VERSION 5.7 ;
BUSBITCHARS "[]" ;
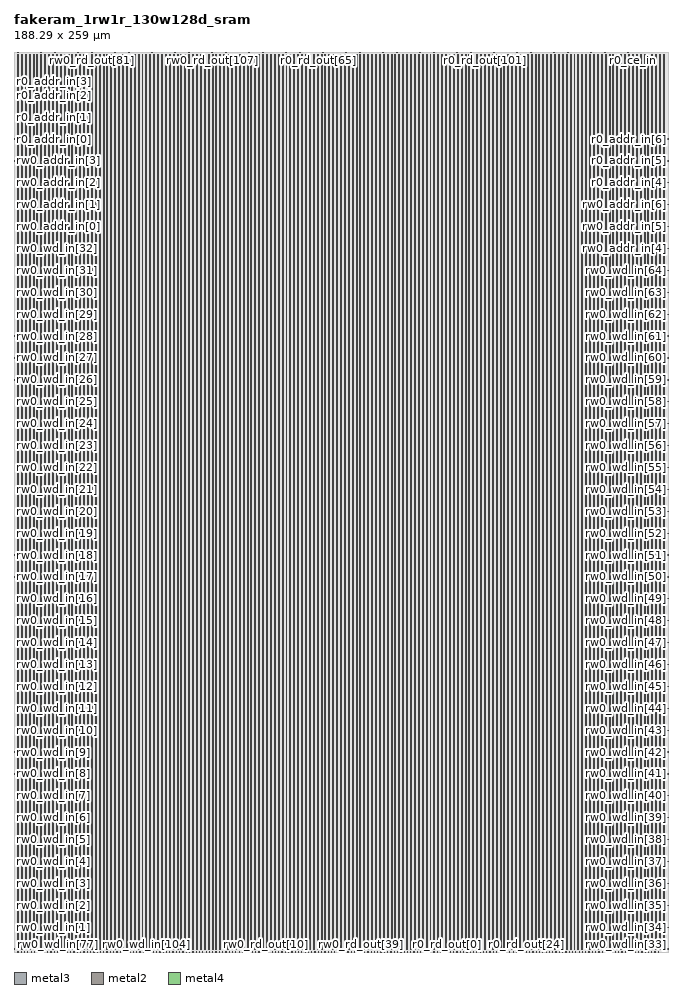
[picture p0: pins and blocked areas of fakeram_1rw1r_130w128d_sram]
MACRO fakeram_1rw1r_130w128d_sram
  FOREIGN fakeram_1rw1r_130w128d_sram 0 0 ;
  SYMMETRY X Y R90 ;
  SIZE 188.290 BY 259.000 ;
  CLASS BLOCK ;
  PIN rw0_wd_in[0]
    DIRECTION INPUT ;
    USE SIGNAL ;
    SHAPE ABUTMENT ;
    PORT
      LAYER metal3 ;
      RECT 0.000 0.805 0.210 0.875 ;
    END
  END rw0_wd_in[0]
  PIN rw0_wd_in[1]
    DIRECTION INPUT ;
    USE SIGNAL ;
    SHAPE ABUTMENT ;
    PORT
      LAYER metal3 ;
      RECT 0.000 7.105 0.210 7.175 ;
    END
  END rw0_wd_in[1]
  PIN rw0_wd_in[2]
    DIRECTION INPUT ;
    USE SIGNAL ;
    SHAPE ABUTMENT ;
    PORT
      LAYER metal3 ;
      RECT 0.000 13.405 0.210 13.475 ;
    END
  END rw0_wd_in[2]
  PIN rw0_wd_in[3]
    DIRECTION INPUT ;
    USE SIGNAL ;
    SHAPE ABUTMENT ;
    PORT
      LAYER metal3 ;
      RECT 0.000 19.705 0.210 19.775 ;
    END
  END rw0_wd_in[3]
  PIN rw0_wd_in[4]
    DIRECTION INPUT ;
    USE SIGNAL ;
    SHAPE ABUTMENT ;
    PORT
      LAYER metal3 ;
      RECT 0.000 26.005 0.210 26.075 ;
    END
  END rw0_wd_in[4]
  PIN rw0_wd_in[5]
    DIRECTION INPUT ;
    USE SIGNAL ;
    SHAPE ABUTMENT ;
    PORT
      LAYER metal3 ;
      RECT 0.000 32.305 0.210 32.375 ;
    END
  END rw0_wd_in[5]
  PIN rw0_wd_in[6]
    DIRECTION INPUT ;
    USE SIGNAL ;
    SHAPE ABUTMENT ;
    PORT
      LAYER metal3 ;
      RECT 0.000 38.605 0.210 38.675 ;
    END
  END rw0_wd_in[6]
  PIN rw0_wd_in[7]
    DIRECTION INPUT ;
    USE SIGNAL ;
    SHAPE ABUTMENT ;
    PORT
      LAYER metal3 ;
      RECT 0.000 44.905 0.210 44.975 ;
    END
  END rw0_wd_in[7]
  PIN rw0_wd_in[8]
    DIRECTION INPUT ;
    USE SIGNAL ;
    SHAPE ABUTMENT ;
    PORT
      LAYER metal3 ;
      RECT 0.000 51.205 0.210 51.275 ;
    END
  END rw0_wd_in[8]
  PIN rw0_wd_in[9]
    DIRECTION INPUT ;
    USE SIGNAL ;
    SHAPE ABUTMENT ;
    PORT
      LAYER metal3 ;
      RECT 0.000 57.505 0.210 57.575 ;
    END
  END rw0_wd_in[9]
  PIN rw0_wd_in[10]
    DIRECTION INPUT ;
    USE SIGNAL ;
    SHAPE ABUTMENT ;
    PORT
      LAYER metal3 ;
      RECT 0.000 63.805 0.210 63.875 ;
    END
  END rw0_wd_in[10]
  PIN rw0_wd_in[11]
    DIRECTION INPUT ;
    USE SIGNAL ;
    SHAPE ABUTMENT ;
    PORT
      LAYER metal3 ;
      RECT 0.000 70.105 0.210 70.175 ;
    END
  END rw0_wd_in[11]
  PIN rw0_wd_in[12]
    DIRECTION INPUT ;
    USE SIGNAL ;
    SHAPE ABUTMENT ;
    PORT
      LAYER metal3 ;
      RECT 0.000 76.405 0.210 76.475 ;
    END
  END rw0_wd_in[12]
  PIN rw0_wd_in[13]
    DIRECTION INPUT ;
    USE SIGNAL ;
    SHAPE ABUTMENT ;
    PORT
      LAYER metal3 ;
      RECT 0.000 82.705 0.210 82.775 ;
    END
  END rw0_wd_in[13]
  PIN rw0_wd_in[14]
    DIRECTION INPUT ;
    USE SIGNAL ;
    SHAPE ABUTMENT ;
    PORT
      LAYER metal3 ;
      RECT 0.000 89.005 0.210 89.075 ;
    END
  END rw0_wd_in[14]
  PIN rw0_wd_in[15]
    DIRECTION INPUT ;
    USE SIGNAL ;
    SHAPE ABUTMENT ;
    PORT
      LAYER metal3 ;
      RECT 0.000 95.305 0.210 95.375 ;
    END
  END rw0_wd_in[15]
  PIN rw0_wd_in[16]
    DIRECTION INPUT ;
    USE SIGNAL ;
    SHAPE ABUTMENT ;
    PORT
      LAYER metal3 ;
      RECT 0.000 101.605 0.210 101.675 ;
    END
  END rw0_wd_in[16]
  PIN rw0_wd_in[17]
    DIRECTION INPUT ;
    USE SIGNAL ;
    SHAPE ABUTMENT ;
    PORT
      LAYER metal3 ;
      RECT 0.000 107.905 0.210 107.975 ;
    END
  END rw0_wd_in[17]
  PIN rw0_wd_in[18]
    DIRECTION INPUT ;
    USE SIGNAL ;
    SHAPE ABUTMENT ;
    PORT
      LAYER metal3 ;
      RECT 0.000 114.205 0.210 114.275 ;
    END
  END rw0_wd_in[18]
  PIN rw0_wd_in[19]
    DIRECTION INPUT ;
    USE SIGNAL ;
    SHAPE ABUTMENT ;
    PORT
      LAYER metal3 ;
      RECT 0.000 120.505 0.210 120.575 ;
    END
  END rw0_wd_in[19]
  PIN rw0_wd_in[20]
    DIRECTION INPUT ;
    USE SIGNAL ;
    SHAPE ABUTMENT ;
    PORT
      LAYER metal3 ;
      RECT 0.000 126.805 0.210 126.875 ;
    END
  END rw0_wd_in[20]
  PIN rw0_wd_in[21]
    DIRECTION INPUT ;
    USE SIGNAL ;
    SHAPE ABUTMENT ;
    PORT
      LAYER metal3 ;
      RECT 0.000 133.105 0.210 133.175 ;
    END
  END rw0_wd_in[21]
  PIN rw0_wd_in[22]
    DIRECTION INPUT ;
    USE SIGNAL ;
    SHAPE ABUTMENT ;
    PORT
      LAYER metal3 ;
      RECT 0.000 139.405 0.210 139.475 ;
    END
  END rw0_wd_in[22]
  PIN rw0_wd_in[23]
    DIRECTION INPUT ;
    USE SIGNAL ;
    SHAPE ABUTMENT ;
    PORT
      LAYER metal3 ;
      RECT 0.000 145.705 0.210 145.775 ;
    END
  END rw0_wd_in[23]
  PIN rw0_wd_in[24]
    DIRECTION INPUT ;
    USE SIGNAL ;
    SHAPE ABUTMENT ;
    PORT
      LAYER metal3 ;
      RECT 0.000 152.005 0.210 152.075 ;
    END
  END rw0_wd_in[24]
  PIN rw0_wd_in[25]
    DIRECTION INPUT ;
    USE SIGNAL ;
    SHAPE ABUTMENT ;
    PORT
      LAYER metal3 ;
      RECT 0.000 158.305 0.210 158.375 ;
    END
  END rw0_wd_in[25]
  PIN rw0_wd_in[26]
    DIRECTION INPUT ;
    USE SIGNAL ;
    SHAPE ABUTMENT ;
    PORT
      LAYER metal3 ;
      RECT 0.000 164.605 0.210 164.675 ;
    END
  END rw0_wd_in[26]
  PIN rw0_wd_in[27]
    DIRECTION INPUT ;
    USE SIGNAL ;
    SHAPE ABUTMENT ;
    PORT
      LAYER metal3 ;
      RECT 0.000 170.905 0.210 170.975 ;
    END
  END rw0_wd_in[27]
  PIN rw0_wd_in[28]
    DIRECTION INPUT ;
    USE SIGNAL ;
    SHAPE ABUTMENT ;
    PORT
      LAYER metal3 ;
      RECT 0.000 177.205 0.210 177.275 ;
    END
  END rw0_wd_in[28]
  PIN rw0_wd_in[29]
    DIRECTION INPUT ;
    USE SIGNAL ;
    SHAPE ABUTMENT ;
    PORT
      LAYER metal3 ;
      RECT 0.000 183.505 0.210 183.575 ;
    END
  END rw0_wd_in[29]
  PIN rw0_wd_in[30]
    DIRECTION INPUT ;
    USE SIGNAL ;
    SHAPE ABUTMENT ;
    PORT
      LAYER metal3 ;
      RECT 0.000 189.805 0.210 189.875 ;
    END
  END rw0_wd_in[30]
  PIN rw0_wd_in[31]
    DIRECTION INPUT ;
    USE SIGNAL ;
    SHAPE ABUTMENT ;
    PORT
      LAYER metal3 ;
      RECT 0.000 196.105 0.210 196.175 ;
    END
  END rw0_wd_in[31]
  PIN rw0_wd_in[32]
    DIRECTION INPUT ;
    USE SIGNAL ;
    SHAPE ABUTMENT ;
    PORT
      LAYER metal3 ;
      RECT 0.000 202.405 0.210 202.475 ;
    END
  END rw0_wd_in[32]
  PIN rw0_wd_in[33]
    DIRECTION INPUT ;
    USE SIGNAL ;
    SHAPE ABUTMENT ;
    PORT
      LAYER metal3 ;
      RECT 188.080 0.805 188.290 0.875 ;
    END
  END rw0_wd_in[33]
  PIN rw0_wd_in[34]
    DIRECTION INPUT ;
    USE SIGNAL ;
    SHAPE ABUTMENT ;
    PORT
      LAYER metal3 ;
      RECT 188.080 7.105 188.290 7.175 ;
    END
  END rw0_wd_in[34]
  PIN rw0_wd_in[35]
    DIRECTION INPUT ;
    USE SIGNAL ;
    SHAPE ABUTMENT ;
    PORT
      LAYER metal3 ;
      RECT 188.080 13.405 188.290 13.475 ;
    END
  END rw0_wd_in[35]
  PIN rw0_wd_in[36]
    DIRECTION INPUT ;
    USE SIGNAL ;
    SHAPE ABUTMENT ;
    PORT
      LAYER metal3 ;
      RECT 188.080 19.705 188.290 19.775 ;
    END
  END rw0_wd_in[36]
  PIN rw0_wd_in[37]
    DIRECTION INPUT ;
    USE SIGNAL ;
    SHAPE ABUTMENT ;
    PORT
      LAYER metal3 ;
      RECT 188.080 26.005 188.290 26.075 ;
    END
  END rw0_wd_in[37]
  PIN rw0_wd_in[38]
    DIRECTION INPUT ;
    USE SIGNAL ;
    SHAPE ABUTMENT ;
    PORT
      LAYER metal3 ;
      RECT 188.080 32.305 188.290 32.375 ;
    END
  END rw0_wd_in[38]
  PIN rw0_wd_in[39]
    DIRECTION INPUT ;
    USE SIGNAL ;
    SHAPE ABUTMENT ;
    PORT
      LAYER metal3 ;
      RECT 188.080 38.605 188.290 38.675 ;
    END
  END rw0_wd_in[39]
  PIN rw0_wd_in[40]
    DIRECTION INPUT ;
    USE SIGNAL ;
    SHAPE ABUTMENT ;
    PORT
      LAYER metal3 ;
      RECT 188.080 44.905 188.290 44.975 ;
    END
  END rw0_wd_in[40]
  PIN rw0_wd_in[41]
    DIRECTION INPUT ;
    USE SIGNAL ;
    SHAPE ABUTMENT ;
    PORT
      LAYER metal3 ;
      RECT 188.080 51.205 188.290 51.275 ;
    END
  END rw0_wd_in[41]
  PIN rw0_wd_in[42]
    DIRECTION INPUT ;
    USE SIGNAL ;
    SHAPE ABUTMENT ;
    PORT
      LAYER metal3 ;
      RECT 188.080 57.505 188.290 57.575 ;
    END
  END rw0_wd_in[42]
  PIN rw0_wd_in[43]
    DIRECTION INPUT ;
    USE SIGNAL ;
    SHAPE ABUTMENT ;
    PORT
      LAYER metal3 ;
      RECT 188.080 63.805 188.290 63.875 ;
    END
  END rw0_wd_in[43]
  PIN rw0_wd_in[44]
    DIRECTION INPUT ;
    USE SIGNAL ;
    SHAPE ABUTMENT ;
    PORT
      LAYER metal3 ;
      RECT 188.080 70.105 188.290 70.175 ;
    END
  END rw0_wd_in[44]
  PIN rw0_wd_in[45]
    DIRECTION INPUT ;
    USE SIGNAL ;
    SHAPE ABUTMENT ;
    PORT
      LAYER metal3 ;
      RECT 188.080 76.405 188.290 76.475 ;
    END
  END rw0_wd_in[45]
  PIN rw0_wd_in[46]
    DIRECTION INPUT ;
    USE SIGNAL ;
    SHAPE ABUTMENT ;
    PORT
      LAYER metal3 ;
      RECT 188.080 82.705 188.290 82.775 ;
    END
  END rw0_wd_in[46]
  PIN rw0_wd_in[47]
    DIRECTION INPUT ;
    USE SIGNAL ;
    SHAPE ABUTMENT ;
    PORT
      LAYER metal3 ;
      RECT 188.080 89.005 188.290 89.075 ;
    END
  END rw0_wd_in[47]
  PIN rw0_wd_in[48]
    DIRECTION INPUT ;
    USE SIGNAL ;
    SHAPE ABUTMENT ;
    PORT
      LAYER metal3 ;
      RECT 188.080 95.305 188.290 95.375 ;
    END
  END rw0_wd_in[48]
  PIN rw0_wd_in[49]
    DIRECTION INPUT ;
    USE SIGNAL ;
    SHAPE ABUTMENT ;
    PORT
      LAYER metal3 ;
      RECT 188.080 101.605 188.290 101.675 ;
    END
  END rw0_wd_in[49]
  PIN rw0_wd_in[50]
    DIRECTION INPUT ;
    USE SIGNAL ;
    SHAPE ABUTMENT ;
    PORT
      LAYER metal3 ;
      RECT 188.080 107.905 188.290 107.975 ;
    END
  END rw0_wd_in[50]
  PIN rw0_wd_in[51]
    DIRECTION INPUT ;
    USE SIGNAL ;
    SHAPE ABUTMENT ;
    PORT
      LAYER metal3 ;
      RECT 188.080 114.205 188.290 114.275 ;
    END
  END rw0_wd_in[51]
  PIN rw0_wd_in[52]
    DIRECTION INPUT ;
    USE SIGNAL ;
    SHAPE ABUTMENT ;
    PORT
      LAYER metal3 ;
      RECT 188.080 120.505 188.290 120.575 ;
    END
  END rw0_wd_in[52]
  PIN rw0_wd_in[53]
    DIRECTION INPUT ;
    USE SIGNAL ;
    SHAPE ABUTMENT ;
    PORT
      LAYER metal3 ;
      RECT 188.080 126.805 188.290 126.875 ;
    END
  END rw0_wd_in[53]
  PIN rw0_wd_in[54]
    DIRECTION INPUT ;
    USE SIGNAL ;
    SHAPE ABUTMENT ;
    PORT
      LAYER metal3 ;
      RECT 188.080 133.105 188.290 133.175 ;
    END
  END rw0_wd_in[54]
  PIN rw0_wd_in[55]
    DIRECTION INPUT ;
    USE SIGNAL ;
    SHAPE ABUTMENT ;
    PORT
      LAYER metal3 ;
      RECT 188.080 139.405 188.290 139.475 ;
    END
  END rw0_wd_in[55]
  PIN rw0_wd_in[56]
    DIRECTION INPUT ;
    USE SIGNAL ;
    SHAPE ABUTMENT ;
    PORT
      LAYER metal3 ;
      RECT 188.080 145.705 188.290 145.775 ;
    END
  END rw0_wd_in[56]
  PIN rw0_wd_in[57]
    DIRECTION INPUT ;
    USE SIGNAL ;
    SHAPE ABUTMENT ;
    PORT
      LAYER metal3 ;
      RECT 188.080 152.005 188.290 152.075 ;
    END
  END rw0_wd_in[57]
  PIN rw0_wd_in[58]
    DIRECTION INPUT ;
    USE SIGNAL ;
    SHAPE ABUTMENT ;
    PORT
      LAYER metal3 ;
      RECT 188.080 158.305 188.290 158.375 ;
    END
  END rw0_wd_in[58]
  PIN rw0_wd_in[59]
    DIRECTION INPUT ;
    USE SIGNAL ;
    SHAPE ABUTMENT ;
    PORT
      LAYER metal3 ;
      RECT 188.080 164.605 188.290 164.675 ;
    END
  END rw0_wd_in[59]
  PIN rw0_wd_in[60]
    DIRECTION INPUT ;
    USE SIGNAL ;
    SHAPE ABUTMENT ;
    PORT
      LAYER metal3 ;
      RECT 188.080 170.905 188.290 170.975 ;
    END
  END rw0_wd_in[60]
  PIN rw0_wd_in[61]
    DIRECTION INPUT ;
    USE SIGNAL ;
    SHAPE ABUTMENT ;
    PORT
      LAYER metal3 ;
      RECT 188.080 177.205 188.290 177.275 ;
    END
  END rw0_wd_in[61]
  PIN rw0_wd_in[62]
    DIRECTION INPUT ;
    USE SIGNAL ;
    SHAPE ABUTMENT ;
    PORT
      LAYER metal3 ;
      RECT 188.080 183.505 188.290 183.575 ;
    END
  END rw0_wd_in[62]
  PIN rw0_wd_in[63]
    DIRECTION INPUT ;
    USE SIGNAL ;
    SHAPE ABUTMENT ;
    PORT
      LAYER metal3 ;
      RECT 188.080 189.805 188.290 189.875 ;
    END
  END rw0_wd_in[63]
  PIN rw0_wd_in[64]
    DIRECTION INPUT ;
    USE SIGNAL ;
    SHAPE ABUTMENT ;
    PORT
      LAYER metal3 ;
      RECT 188.080 196.105 188.290 196.175 ;
    END
  END rw0_wd_in[64]
  PIN rw0_wd_in[65]
    DIRECTION INPUT ;
    USE SIGNAL ;
    SHAPE ABUTMENT ;
    PORT
      LAYER metal2 ;
      RECT 1.105 0.000 1.175 0.210 ;
    END
  END rw0_wd_in[65]
  PIN rw0_wd_in[66]
    DIRECTION INPUT ;
    USE SIGNAL ;
    SHAPE ABUTMENT ;
    PORT
      LAYER metal2 ;
      RECT 2.055 0.000 2.125 0.210 ;
    END
  END rw0_wd_in[66]
  PIN rw0_wd_in[67]
    DIRECTION INPUT ;
    USE SIGNAL ;
    SHAPE ABUTMENT ;
    PORT
      LAYER metal2 ;
      RECT 3.005 0.000 3.075 0.210 ;
    END
  END rw0_wd_in[67]
  PIN rw0_wd_in[68]
    DIRECTION INPUT ;
    USE SIGNAL ;
    SHAPE ABUTMENT ;
    PORT
      LAYER metal2 ;
      RECT 3.955 0.000 4.025 0.210 ;
    END
  END rw0_wd_in[68]
  PIN rw0_wd_in[69]
    DIRECTION INPUT ;
    USE SIGNAL ;
    SHAPE ABUTMENT ;
    PORT
      LAYER metal2 ;
      RECT 4.905 0.000 4.975 0.210 ;
    END
  END rw0_wd_in[69]
  PIN rw0_wd_in[70]
    DIRECTION INPUT ;
    USE SIGNAL ;
    SHAPE ABUTMENT ;
    PORT
      LAYER metal2 ;
      RECT 5.855 0.000 5.925 0.210 ;
    END
  END rw0_wd_in[70]
  PIN rw0_wd_in[71]
    DIRECTION INPUT ;
    USE SIGNAL ;
    SHAPE ABUTMENT ;
    PORT
      LAYER metal2 ;
      RECT 6.805 0.000 6.875 0.210 ;
    END
  END rw0_wd_in[71]
  PIN rw0_wd_in[72]
    DIRECTION INPUT ;
    USE SIGNAL ;
    SHAPE ABUTMENT ;
    PORT
      LAYER metal2 ;
      RECT 7.755 0.000 7.825 0.210 ;
    END
  END rw0_wd_in[72]
  PIN rw0_wd_in[73]
    DIRECTION INPUT ;
    USE SIGNAL ;
    SHAPE ABUTMENT ;
    PORT
      LAYER metal2 ;
      RECT 8.705 0.000 8.775 0.210 ;
    END
  END rw0_wd_in[73]
  PIN rw0_wd_in[74]
    DIRECTION INPUT ;
    USE SIGNAL ;
    SHAPE ABUTMENT ;
    PORT
      LAYER metal2 ;
      RECT 9.655 0.000 9.725 0.210 ;
    END
  END rw0_wd_in[74]
  PIN rw0_wd_in[75]
    DIRECTION INPUT ;
    USE SIGNAL ;
    SHAPE ABUTMENT ;
    PORT
      LAYER metal2 ;
      RECT 10.605 0.000 10.675 0.210 ;
    END
  END rw0_wd_in[75]
  PIN rw0_wd_in[76]
    DIRECTION INPUT ;
    USE SIGNAL ;
    SHAPE ABUTMENT ;
    PORT
      LAYER metal2 ;
      RECT 11.555 0.000 11.625 0.210 ;
    END
  END rw0_wd_in[76]
  PIN rw0_wd_in[77]
    DIRECTION INPUT ;
    USE SIGNAL ;
    SHAPE ABUTMENT ;
    PORT
      LAYER metal2 ;
      RECT 12.505 0.000 12.575 0.210 ;
    END
  END rw0_wd_in[77]
  PIN rw0_wd_in[78]
    DIRECTION INPUT ;
    USE SIGNAL ;
    SHAPE ABUTMENT ;
    PORT
      LAYER metal2 ;
      RECT 13.455 0.000 13.525 0.210 ;
    END
  END rw0_wd_in[78]
  PIN rw0_wd_in[79]
    DIRECTION INPUT ;
    USE SIGNAL ;
    SHAPE ABUTMENT ;
    PORT
      LAYER metal2 ;
      RECT 14.405 0.000 14.475 0.210 ;
    END
  END rw0_wd_in[79]
  PIN rw0_wd_in[80]
    DIRECTION INPUT ;
    USE SIGNAL ;
    SHAPE ABUTMENT ;
    PORT
      LAYER metal2 ;
      RECT 15.355 0.000 15.425 0.210 ;
    END
  END rw0_wd_in[80]
  PIN rw0_wd_in[81]
    DIRECTION INPUT ;
    USE SIGNAL ;
    SHAPE ABUTMENT ;
    PORT
      LAYER metal2 ;
      RECT 16.305 0.000 16.375 0.210 ;
    END
  END rw0_wd_in[81]
  PIN rw0_wd_in[82]
    DIRECTION INPUT ;
    USE SIGNAL ;
    SHAPE ABUTMENT ;
    PORT
      LAYER metal2 ;
      RECT 17.255 0.000 17.325 0.210 ;
    END
  END rw0_wd_in[82]
  PIN rw0_wd_in[83]
    DIRECTION INPUT ;
    USE SIGNAL ;
    SHAPE ABUTMENT ;
    PORT
      LAYER metal2 ;
      RECT 18.205 0.000 18.275 0.210 ;
    END
  END rw0_wd_in[83]
  PIN rw0_wd_in[84]
    DIRECTION INPUT ;
    USE SIGNAL ;
    SHAPE ABUTMENT ;
    PORT
      LAYER metal2 ;
      RECT 19.155 0.000 19.225 0.210 ;
    END
  END rw0_wd_in[84]
  PIN rw0_wd_in[85]
    DIRECTION INPUT ;
    USE SIGNAL ;
    SHAPE ABUTMENT ;
    PORT
      LAYER metal2 ;
      RECT 20.105 0.000 20.175 0.210 ;
    END
  END rw0_wd_in[85]
  PIN rw0_wd_in[86]
    DIRECTION INPUT ;
    USE SIGNAL ;
    SHAPE ABUTMENT ;
    PORT
      LAYER metal2 ;
      RECT 21.055 0.000 21.125 0.210 ;
    END
  END rw0_wd_in[86]
  PIN rw0_wd_in[87]
    DIRECTION INPUT ;
    USE SIGNAL ;
    SHAPE ABUTMENT ;
    PORT
      LAYER metal2 ;
      RECT 22.005 0.000 22.075 0.210 ;
    END
  END rw0_wd_in[87]
  PIN rw0_wd_in[88]
    DIRECTION INPUT ;
    USE SIGNAL ;
    SHAPE ABUTMENT ;
    PORT
      LAYER metal2 ;
      RECT 22.955 0.000 23.025 0.210 ;
    END
  END rw0_wd_in[88]
  PIN rw0_wd_in[89]
    DIRECTION INPUT ;
    USE SIGNAL ;
    SHAPE ABUTMENT ;
    PORT
      LAYER metal2 ;
      RECT 23.905 0.000 23.975 0.210 ;
    END
  END rw0_wd_in[89]
  PIN rw0_wd_in[90]
    DIRECTION INPUT ;
    USE SIGNAL ;
    SHAPE ABUTMENT ;
    PORT
      LAYER metal2 ;
      RECT 24.855 0.000 24.925 0.210 ;
    END
  END rw0_wd_in[90]
  PIN rw0_wd_in[91]
    DIRECTION INPUT ;
    USE SIGNAL ;
    SHAPE ABUTMENT ;
    PORT
      LAYER metal2 ;
      RECT 25.805 0.000 25.875 0.210 ;
    END
  END rw0_wd_in[91]
  PIN rw0_wd_in[92]
    DIRECTION INPUT ;
    USE SIGNAL ;
    SHAPE ABUTMENT ;
    PORT
      LAYER metal2 ;
      RECT 26.755 0.000 26.825 0.210 ;
    END
  END rw0_wd_in[92]
  PIN rw0_wd_in[93]
    DIRECTION INPUT ;
    USE SIGNAL ;
    SHAPE ABUTMENT ;
    PORT
      LAYER metal2 ;
      RECT 27.705 0.000 27.775 0.210 ;
    END
  END rw0_wd_in[93]
  PIN rw0_wd_in[94]
    DIRECTION INPUT ;
    USE SIGNAL ;
    SHAPE ABUTMENT ;
    PORT
      LAYER metal2 ;
      RECT 28.655 0.000 28.725 0.210 ;
    END
  END rw0_wd_in[94]
  PIN rw0_wd_in[95]
    DIRECTION INPUT ;
    USE SIGNAL ;
    SHAPE ABUTMENT ;
    PORT
      LAYER metal2 ;
      RECT 29.605 0.000 29.675 0.210 ;
    END
  END rw0_wd_in[95]
  PIN rw0_wd_in[96]
    DIRECTION INPUT ;
    USE SIGNAL ;
    SHAPE ABUTMENT ;
    PORT
      LAYER metal2 ;
      RECT 30.555 0.000 30.625 0.210 ;
    END
  END rw0_wd_in[96]
  PIN rw0_wd_in[97]
    DIRECTION INPUT ;
    USE SIGNAL ;
    SHAPE ABUTMENT ;
    PORT
      LAYER metal2 ;
      RECT 31.505 0.000 31.575 0.210 ;
    END
  END rw0_wd_in[97]
  PIN rw0_wd_in[98]
    DIRECTION INPUT ;
    USE SIGNAL ;
    SHAPE ABUTMENT ;
    PORT
      LAYER metal2 ;
      RECT 32.455 0.000 32.525 0.210 ;
    END
  END rw0_wd_in[98]
  PIN rw0_wd_in[99]
    DIRECTION INPUT ;
    USE SIGNAL ;
    SHAPE ABUTMENT ;
    PORT
      LAYER metal2 ;
      RECT 33.405 0.000 33.475 0.210 ;
    END
  END rw0_wd_in[99]
  PIN rw0_wd_in[100]
    DIRECTION INPUT ;
    USE SIGNAL ;
    SHAPE ABUTMENT ;
    PORT
      LAYER metal2 ;
      RECT 34.355 0.000 34.425 0.210 ;
    END
  END rw0_wd_in[100]
  PIN rw0_wd_in[101]
    DIRECTION INPUT ;
    USE SIGNAL ;
    SHAPE ABUTMENT ;
    PORT
      LAYER metal2 ;
      RECT 35.305 0.000 35.375 0.210 ;
    END
  END rw0_wd_in[101]
  PIN rw0_wd_in[102]
    DIRECTION INPUT ;
    USE SIGNAL ;
    SHAPE ABUTMENT ;
    PORT
      LAYER metal2 ;
      RECT 36.255 0.000 36.325 0.210 ;
    END
  END rw0_wd_in[102]
  PIN rw0_wd_in[103]
    DIRECTION INPUT ;
    USE SIGNAL ;
    SHAPE ABUTMENT ;
    PORT
      LAYER metal2 ;
      RECT 37.205 0.000 37.275 0.210 ;
    END
  END rw0_wd_in[103]
  PIN rw0_wd_in[104]
    DIRECTION INPUT ;
    USE SIGNAL ;
    SHAPE ABUTMENT ;
    PORT
      LAYER metal2 ;
      RECT 38.155 0.000 38.225 0.210 ;
    END
  END rw0_wd_in[104]
  PIN rw0_wd_in[105]
    DIRECTION INPUT ;
    USE SIGNAL ;
    SHAPE ABUTMENT ;
    PORT
      LAYER metal2 ;
      RECT 39.105 0.000 39.175 0.210 ;
    END
  END rw0_wd_in[105]
  PIN rw0_wd_in[106]
    DIRECTION INPUT ;
    USE SIGNAL ;
    SHAPE ABUTMENT ;
    PORT
      LAYER metal2 ;
      RECT 40.055 0.000 40.125 0.210 ;
    END
  END rw0_wd_in[106]
  PIN rw0_wd_in[107]
    DIRECTION INPUT ;
    USE SIGNAL ;
    SHAPE ABUTMENT ;
    PORT
      LAYER metal2 ;
      RECT 41.005 0.000 41.075 0.210 ;
    END
  END rw0_wd_in[107]
  PIN rw0_wd_in[108]
    DIRECTION INPUT ;
    USE SIGNAL ;
    SHAPE ABUTMENT ;
    PORT
      LAYER metal2 ;
      RECT 41.955 0.000 42.025 0.210 ;
    END
  END rw0_wd_in[108]
  PIN rw0_wd_in[109]
    DIRECTION INPUT ;
    USE SIGNAL ;
    SHAPE ABUTMENT ;
    PORT
      LAYER metal2 ;
      RECT 42.905 0.000 42.975 0.210 ;
    END
  END rw0_wd_in[109]
  PIN rw0_wd_in[110]
    DIRECTION INPUT ;
    USE SIGNAL ;
    SHAPE ABUTMENT ;
    PORT
      LAYER metal2 ;
      RECT 43.855 0.000 43.925 0.210 ;
    END
  END rw0_wd_in[110]
  PIN rw0_wd_in[111]
    DIRECTION INPUT ;
    USE SIGNAL ;
    SHAPE ABUTMENT ;
    PORT
      LAYER metal2 ;
      RECT 44.805 0.000 44.875 0.210 ;
    END
  END rw0_wd_in[111]
  PIN rw0_wd_in[112]
    DIRECTION INPUT ;
    USE SIGNAL ;
    SHAPE ABUTMENT ;
    PORT
      LAYER metal2 ;
      RECT 45.755 0.000 45.825 0.210 ;
    END
  END rw0_wd_in[112]
  PIN rw0_wd_in[113]
    DIRECTION INPUT ;
    USE SIGNAL ;
    SHAPE ABUTMENT ;
    PORT
      LAYER metal2 ;
      RECT 46.705 0.000 46.775 0.210 ;
    END
  END rw0_wd_in[113]
  PIN rw0_wd_in[114]
    DIRECTION INPUT ;
    USE SIGNAL ;
    SHAPE ABUTMENT ;
    PORT
      LAYER metal2 ;
      RECT 47.655 0.000 47.725 0.210 ;
    END
  END rw0_wd_in[114]
  PIN rw0_wd_in[115]
    DIRECTION INPUT ;
    USE SIGNAL ;
    SHAPE ABUTMENT ;
    PORT
      LAYER metal2 ;
      RECT 48.605 0.000 48.675 0.210 ;
    END
  END rw0_wd_in[115]
  PIN rw0_wd_in[116]
    DIRECTION INPUT ;
    USE SIGNAL ;
    SHAPE ABUTMENT ;
    PORT
      LAYER metal2 ;
      RECT 49.555 0.000 49.625 0.210 ;
    END
  END rw0_wd_in[116]
  PIN rw0_wd_in[117]
    DIRECTION INPUT ;
    USE SIGNAL ;
    SHAPE ABUTMENT ;
    PORT
      LAYER metal2 ;
      RECT 50.505 0.000 50.575 0.210 ;
    END
  END rw0_wd_in[117]
  PIN rw0_wd_in[118]
    DIRECTION INPUT ;
    USE SIGNAL ;
    SHAPE ABUTMENT ;
    PORT
      LAYER metal2 ;
      RECT 51.455 0.000 51.525 0.210 ;
    END
  END rw0_wd_in[118]
  PIN rw0_wd_in[119]
    DIRECTION INPUT ;
    USE SIGNAL ;
    SHAPE ABUTMENT ;
    PORT
      LAYER metal2 ;
      RECT 52.405 0.000 52.475 0.210 ;
    END
  END rw0_wd_in[119]
  PIN rw0_wd_in[120]
    DIRECTION INPUT ;
    USE SIGNAL ;
    SHAPE ABUTMENT ;
    PORT
      LAYER metal2 ;
      RECT 53.355 0.000 53.425 0.210 ;
    END
  END rw0_wd_in[120]
  PIN rw0_wd_in[121]
    DIRECTION INPUT ;
    USE SIGNAL ;
    SHAPE ABUTMENT ;
    PORT
      LAYER metal2 ;
      RECT 54.305 0.000 54.375 0.210 ;
    END
  END rw0_wd_in[121]
  PIN rw0_wd_in[122]
    DIRECTION INPUT ;
    USE SIGNAL ;
    SHAPE ABUTMENT ;
    PORT
      LAYER metal2 ;
      RECT 55.255 0.000 55.325 0.210 ;
    END
  END rw0_wd_in[122]
  PIN rw0_wd_in[123]
    DIRECTION INPUT ;
    USE SIGNAL ;
    SHAPE ABUTMENT ;
    PORT
      LAYER metal2 ;
      RECT 56.205 0.000 56.275 0.210 ;
    END
  END rw0_wd_in[123]
  PIN rw0_wd_in[124]
    DIRECTION INPUT ;
    USE SIGNAL ;
    SHAPE ABUTMENT ;
    PORT
      LAYER metal2 ;
      RECT 57.155 0.000 57.225 0.210 ;
    END
  END rw0_wd_in[124]
  PIN rw0_wd_in[125]
    DIRECTION INPUT ;
    USE SIGNAL ;
    SHAPE ABUTMENT ;
    PORT
      LAYER metal2 ;
      RECT 58.105 0.000 58.175 0.210 ;
    END
  END rw0_wd_in[125]
  PIN rw0_wd_in[126]
    DIRECTION INPUT ;
    USE SIGNAL ;
    SHAPE ABUTMENT ;
    PORT
      LAYER metal2 ;
      RECT 59.055 0.000 59.125 0.210 ;
    END
  END rw0_wd_in[126]
  PIN rw0_wd_in[127]
    DIRECTION INPUT ;
    USE SIGNAL ;
    SHAPE ABUTMENT ;
    PORT
      LAYER metal2 ;
      RECT 60.005 0.000 60.075 0.210 ;
    END
  END rw0_wd_in[127]
  PIN rw0_wd_in[128]
    DIRECTION INPUT ;
    USE SIGNAL ;
    SHAPE ABUTMENT ;
    PORT
      LAYER metal2 ;
      RECT 60.955 0.000 61.025 0.210 ;
    END
  END rw0_wd_in[128]
  PIN rw0_wd_in[129]
    DIRECTION INPUT ;
    USE SIGNAL ;
    SHAPE ABUTMENT ;
    PORT
      LAYER metal2 ;
      RECT 61.905 0.000 61.975 0.210 ;
    END
  END rw0_wd_in[129]
  PIN rw0_rd_out[0]
    DIRECTION OUTPUT ;
    USE SIGNAL ;
    SHAPE ABUTMENT ;
    PORT
      LAYER metal2 ;
      RECT 62.855 0.000 62.925 0.210 ;
    END
  END rw0_rd_out[0]
  PIN rw0_rd_out[1]
    DIRECTION OUTPUT ;
    USE SIGNAL ;
    SHAPE ABUTMENT ;
    PORT
      LAYER metal2 ;
      RECT 63.805 0.000 63.875 0.210 ;
    END
  END rw0_rd_out[1]
  PIN rw0_rd_out[2]
    DIRECTION OUTPUT ;
    USE SIGNAL ;
    SHAPE ABUTMENT ;
    PORT
      LAYER metal2 ;
      RECT 64.755 0.000 64.825 0.210 ;
    END
  END rw0_rd_out[2]
  PIN rw0_rd_out[3]
    DIRECTION OUTPUT ;
    USE SIGNAL ;
    SHAPE ABUTMENT ;
    PORT
      LAYER metal2 ;
      RECT 65.705 0.000 65.775 0.210 ;
    END
  END rw0_rd_out[3]
  PIN rw0_rd_out[4]
    DIRECTION OUTPUT ;
    USE SIGNAL ;
    SHAPE ABUTMENT ;
    PORT
      LAYER metal2 ;
      RECT 66.655 0.000 66.725 0.210 ;
    END
  END rw0_rd_out[4]
  PIN rw0_rd_out[5]
    DIRECTION OUTPUT ;
    USE SIGNAL ;
    SHAPE ABUTMENT ;
    PORT
      LAYER metal2 ;
      RECT 67.605 0.000 67.675 0.210 ;
    END
  END rw0_rd_out[5]
  PIN rw0_rd_out[6]
    DIRECTION OUTPUT ;
    USE SIGNAL ;
    SHAPE ABUTMENT ;
    PORT
      LAYER metal2 ;
      RECT 68.555 0.000 68.625 0.210 ;
    END
  END rw0_rd_out[6]
  PIN rw0_rd_out[7]
    DIRECTION OUTPUT ;
    USE SIGNAL ;
    SHAPE ABUTMENT ;
    PORT
      LAYER metal2 ;
      RECT 69.505 0.000 69.575 0.210 ;
    END
  END rw0_rd_out[7]
  PIN rw0_rd_out[8]
    DIRECTION OUTPUT ;
    USE SIGNAL ;
    SHAPE ABUTMENT ;
    PORT
      LAYER metal2 ;
      RECT 70.455 0.000 70.525 0.210 ;
    END
  END rw0_rd_out[8]
  PIN rw0_rd_out[9]
    DIRECTION OUTPUT ;
    USE SIGNAL ;
    SHAPE ABUTMENT ;
    PORT
      LAYER metal2 ;
      RECT 71.405 0.000 71.475 0.210 ;
    END
  END rw0_rd_out[9]
  PIN rw0_rd_out[10]
    DIRECTION OUTPUT ;
    USE SIGNAL ;
    SHAPE ABUTMENT ;
    PORT
      LAYER metal2 ;
      RECT 72.355 0.000 72.425 0.210 ;
    END
  END rw0_rd_out[10]
  PIN rw0_rd_out[11]
    DIRECTION OUTPUT ;
    USE SIGNAL ;
    SHAPE ABUTMENT ;
    PORT
      LAYER metal2 ;
      RECT 73.305 0.000 73.375 0.210 ;
    END
  END rw0_rd_out[11]
  PIN rw0_rd_out[12]
    DIRECTION OUTPUT ;
    USE SIGNAL ;
    SHAPE ABUTMENT ;
    PORT
      LAYER metal2 ;
      RECT 74.255 0.000 74.325 0.210 ;
    END
  END rw0_rd_out[12]
  PIN rw0_rd_out[13]
    DIRECTION OUTPUT ;
    USE SIGNAL ;
    SHAPE ABUTMENT ;
    PORT
      LAYER metal2 ;
      RECT 75.205 0.000 75.275 0.210 ;
    END
  END rw0_rd_out[13]
  PIN rw0_rd_out[14]
    DIRECTION OUTPUT ;
    USE SIGNAL ;
    SHAPE ABUTMENT ;
    PORT
      LAYER metal2 ;
      RECT 76.155 0.000 76.225 0.210 ;
    END
  END rw0_rd_out[14]
  PIN rw0_rd_out[15]
    DIRECTION OUTPUT ;
    USE SIGNAL ;
    SHAPE ABUTMENT ;
    PORT
      LAYER metal2 ;
      RECT 77.105 0.000 77.175 0.210 ;
    END
  END rw0_rd_out[15]
  PIN rw0_rd_out[16]
    DIRECTION OUTPUT ;
    USE SIGNAL ;
    SHAPE ABUTMENT ;
    PORT
      LAYER metal2 ;
      RECT 78.055 0.000 78.125 0.210 ;
    END
  END rw0_rd_out[16]
  PIN rw0_rd_out[17]
    DIRECTION OUTPUT ;
    USE SIGNAL ;
    SHAPE ABUTMENT ;
    PORT
      LAYER metal2 ;
      RECT 79.005 0.000 79.075 0.210 ;
    END
  END rw0_rd_out[17]
  PIN rw0_rd_out[18]
    DIRECTION OUTPUT ;
    USE SIGNAL ;
    SHAPE ABUTMENT ;
    PORT
      LAYER metal2 ;
      RECT 79.955 0.000 80.025 0.210 ;
    END
  END rw0_rd_out[18]
  PIN rw0_rd_out[19]
    DIRECTION OUTPUT ;
    USE SIGNAL ;
    SHAPE ABUTMENT ;
    PORT
      LAYER metal2 ;
      RECT 80.905 0.000 80.975 0.210 ;
    END
  END rw0_rd_out[19]
  PIN rw0_rd_out[20]
    DIRECTION OUTPUT ;
    USE SIGNAL ;
    SHAPE ABUTMENT ;
    PORT
      LAYER metal2 ;
      RECT 81.855 0.000 81.925 0.210 ;
    END
  END rw0_rd_out[20]
  PIN rw0_rd_out[21]
    DIRECTION OUTPUT ;
    USE SIGNAL ;
    SHAPE ABUTMENT ;
    PORT
      LAYER metal2 ;
      RECT 82.805 0.000 82.875 0.210 ;
    END
  END rw0_rd_out[21]
  PIN rw0_rd_out[22]
    DIRECTION OUTPUT ;
    USE SIGNAL ;
    SHAPE ABUTMENT ;
    PORT
      LAYER metal2 ;
      RECT 83.755 0.000 83.825 0.210 ;
    END
  END rw0_rd_out[22]
  PIN rw0_rd_out[23]
    DIRECTION OUTPUT ;
    USE SIGNAL ;
    SHAPE ABUTMENT ;
    PORT
      LAYER metal2 ;
      RECT 84.705 0.000 84.775 0.210 ;
    END
  END rw0_rd_out[23]
  PIN rw0_rd_out[24]
    DIRECTION OUTPUT ;
    USE SIGNAL ;
    SHAPE ABUTMENT ;
    PORT
      LAYER metal2 ;
      RECT 85.655 0.000 85.725 0.210 ;
    END
  END rw0_rd_out[24]
  PIN rw0_rd_out[25]
    DIRECTION OUTPUT ;
    USE SIGNAL ;
    SHAPE ABUTMENT ;
    PORT
      LAYER metal2 ;
      RECT 86.605 0.000 86.675 0.210 ;
    END
  END rw0_rd_out[25]
  PIN rw0_rd_out[26]
    DIRECTION OUTPUT ;
    USE SIGNAL ;
    SHAPE ABUTMENT ;
    PORT
      LAYER metal2 ;
      RECT 87.555 0.000 87.625 0.210 ;
    END
  END rw0_rd_out[26]
  PIN rw0_rd_out[27]
    DIRECTION OUTPUT ;
    USE SIGNAL ;
    SHAPE ABUTMENT ;
    PORT
      LAYER metal2 ;
      RECT 88.505 0.000 88.575 0.210 ;
    END
  END rw0_rd_out[27]
  PIN rw0_rd_out[28]
    DIRECTION OUTPUT ;
    USE SIGNAL ;
    SHAPE ABUTMENT ;
    PORT
      LAYER metal2 ;
      RECT 89.455 0.000 89.525 0.210 ;
    END
  END rw0_rd_out[28]
  PIN rw0_rd_out[29]
    DIRECTION OUTPUT ;
    USE SIGNAL ;
    SHAPE ABUTMENT ;
    PORT
      LAYER metal2 ;
      RECT 90.405 0.000 90.475 0.210 ;
    END
  END rw0_rd_out[29]
  PIN rw0_rd_out[30]
    DIRECTION OUTPUT ;
    USE SIGNAL ;
    SHAPE ABUTMENT ;
    PORT
      LAYER metal2 ;
      RECT 91.355 0.000 91.425 0.210 ;
    END
  END rw0_rd_out[30]
  PIN rw0_rd_out[31]
    DIRECTION OUTPUT ;
    USE SIGNAL ;
    SHAPE ABUTMENT ;
    PORT
      LAYER metal2 ;
      RECT 92.305 0.000 92.375 0.210 ;
    END
  END rw0_rd_out[31]
  PIN rw0_rd_out[32]
    DIRECTION OUTPUT ;
    USE SIGNAL ;
    SHAPE ABUTMENT ;
    PORT
      LAYER metal2 ;
      RECT 93.255 0.000 93.325 0.210 ;
    END
  END rw0_rd_out[32]
  PIN rw0_rd_out[33]
    DIRECTION OUTPUT ;
    USE SIGNAL ;
    SHAPE ABUTMENT ;
    PORT
      LAYER metal2 ;
      RECT 94.205 0.000 94.275 0.210 ;
    END
  END rw0_rd_out[33]
  PIN rw0_rd_out[34]
    DIRECTION OUTPUT ;
    USE SIGNAL ;
    SHAPE ABUTMENT ;
    PORT
      LAYER metal2 ;
      RECT 95.155 0.000 95.225 0.210 ;
    END
  END rw0_rd_out[34]
  PIN rw0_rd_out[35]
    DIRECTION OUTPUT ;
    USE SIGNAL ;
    SHAPE ABUTMENT ;
    PORT
      LAYER metal2 ;
      RECT 96.105 0.000 96.175 0.210 ;
    END
  END rw0_rd_out[35]
  PIN rw0_rd_out[36]
    DIRECTION OUTPUT ;
    USE SIGNAL ;
    SHAPE ABUTMENT ;
    PORT
      LAYER metal2 ;
      RECT 97.055 0.000 97.125 0.210 ;
    END
  END rw0_rd_out[36]
  PIN rw0_rd_out[37]
    DIRECTION OUTPUT ;
    USE SIGNAL ;
    SHAPE ABUTMENT ;
    PORT
      LAYER metal2 ;
      RECT 98.005 0.000 98.075 0.210 ;
    END
  END rw0_rd_out[37]
  PIN rw0_rd_out[38]
    DIRECTION OUTPUT ;
    USE SIGNAL ;
    SHAPE ABUTMENT ;
    PORT
      LAYER metal2 ;
      RECT 98.955 0.000 99.025 0.210 ;
    END
  END rw0_rd_out[38]
  PIN rw0_rd_out[39]
    DIRECTION OUTPUT ;
    USE SIGNAL ;
    SHAPE ABUTMENT ;
    PORT
      LAYER metal2 ;
      RECT 99.905 0.000 99.975 0.210 ;
    END
  END rw0_rd_out[39]
  PIN rw0_rd_out[40]
    DIRECTION OUTPUT ;
    USE SIGNAL ;
    SHAPE ABUTMENT ;
    PORT
      LAYER metal2 ;
      RECT 100.855 0.000 100.925 0.210 ;
    END
  END rw0_rd_out[40]
  PIN rw0_rd_out[41]
    DIRECTION OUTPUT ;
    USE SIGNAL ;
    SHAPE ABUTMENT ;
    PORT
      LAYER metal2 ;
      RECT 101.805 0.000 101.875 0.210 ;
    END
  END rw0_rd_out[41]
  PIN rw0_rd_out[42]
    DIRECTION OUTPUT ;
    USE SIGNAL ;
    SHAPE ABUTMENT ;
    PORT
      LAYER metal2 ;
      RECT 102.755 0.000 102.825 0.210 ;
    END
  END rw0_rd_out[42]
  PIN rw0_rd_out[43]
    DIRECTION OUTPUT ;
    USE SIGNAL ;
    SHAPE ABUTMENT ;
    PORT
      LAYER metal2 ;
      RECT 103.705 0.000 103.775 0.210 ;
    END
  END rw0_rd_out[43]
  PIN rw0_rd_out[44]
    DIRECTION OUTPUT ;
    USE SIGNAL ;
    SHAPE ABUTMENT ;
    PORT
      LAYER metal2 ;
      RECT 104.655 0.000 104.725 0.210 ;
    END
  END rw0_rd_out[44]
  PIN rw0_rd_out[45]
    DIRECTION OUTPUT ;
    USE SIGNAL ;
    SHAPE ABUTMENT ;
    PORT
      LAYER metal2 ;
      RECT 105.605 0.000 105.675 0.210 ;
    END
  END rw0_rd_out[45]
  PIN rw0_rd_out[46]
    DIRECTION OUTPUT ;
    USE SIGNAL ;
    SHAPE ABUTMENT ;
    PORT
      LAYER metal2 ;
      RECT 106.555 0.000 106.625 0.210 ;
    END
  END rw0_rd_out[46]
  PIN rw0_rd_out[47]
    DIRECTION OUTPUT ;
    USE SIGNAL ;
    SHAPE ABUTMENT ;
    PORT
      LAYER metal2 ;
      RECT 107.505 0.000 107.575 0.210 ;
    END
  END rw0_rd_out[47]
  PIN rw0_rd_out[48]
    DIRECTION OUTPUT ;
    USE SIGNAL ;
    SHAPE ABUTMENT ;
    PORT
      LAYER metal2 ;
      RECT 108.455 0.000 108.525 0.210 ;
    END
  END rw0_rd_out[48]
  PIN rw0_rd_out[49]
    DIRECTION OUTPUT ;
    USE SIGNAL ;
    SHAPE ABUTMENT ;
    PORT
      LAYER metal2 ;
      RECT 109.405 0.000 109.475 0.210 ;
    END
  END rw0_rd_out[49]
  PIN rw0_rd_out[50]
    DIRECTION OUTPUT ;
    USE SIGNAL ;
    SHAPE ABUTMENT ;
    PORT
      LAYER metal2 ;
      RECT 110.355 0.000 110.425 0.210 ;
    END
  END rw0_rd_out[50]
  PIN rw0_rd_out[51]
    DIRECTION OUTPUT ;
    USE SIGNAL ;
    SHAPE ABUTMENT ;
    PORT
      LAYER metal2 ;
      RECT 111.305 0.000 111.375 0.210 ;
    END
  END rw0_rd_out[51]
  PIN rw0_rd_out[52]
    DIRECTION OUTPUT ;
    USE SIGNAL ;
    SHAPE ABUTMENT ;
    PORT
      LAYER metal2 ;
      RECT 112.255 0.000 112.325 0.210 ;
    END
  END rw0_rd_out[52]
  PIN rw0_rd_out[53]
    DIRECTION OUTPUT ;
    USE SIGNAL ;
    SHAPE ABUTMENT ;
    PORT
      LAYER metal2 ;
      RECT 113.205 0.000 113.275 0.210 ;
    END
  END rw0_rd_out[53]
  PIN rw0_rd_out[54]
    DIRECTION OUTPUT ;
    USE SIGNAL ;
    SHAPE ABUTMENT ;
    PORT
      LAYER metal2 ;
      RECT 114.155 0.000 114.225 0.210 ;
    END
  END rw0_rd_out[54]
  PIN rw0_rd_out[55]
    DIRECTION OUTPUT ;
    USE SIGNAL ;
    SHAPE ABUTMENT ;
    PORT
      LAYER metal2 ;
      RECT 115.105 0.000 115.175 0.210 ;
    END
  END rw0_rd_out[55]
  PIN rw0_rd_out[56]
    DIRECTION OUTPUT ;
    USE SIGNAL ;
    SHAPE ABUTMENT ;
    PORT
      LAYER metal2 ;
      RECT 116.055 0.000 116.125 0.210 ;
    END
  END rw0_rd_out[56]
  PIN rw0_rd_out[57]
    DIRECTION OUTPUT ;
    USE SIGNAL ;
    SHAPE ABUTMENT ;
    PORT
      LAYER metal2 ;
      RECT 117.005 0.000 117.075 0.210 ;
    END
  END rw0_rd_out[57]
  PIN rw0_rd_out[58]
    DIRECTION OUTPUT ;
    USE SIGNAL ;
    SHAPE ABUTMENT ;
    PORT
      LAYER metal2 ;
      RECT 117.955 0.000 118.025 0.210 ;
    END
  END rw0_rd_out[58]
  PIN rw0_rd_out[59]
    DIRECTION OUTPUT ;
    USE SIGNAL ;
    SHAPE ABUTMENT ;
    PORT
      LAYER metal2 ;
      RECT 118.905 0.000 118.975 0.210 ;
    END
  END rw0_rd_out[59]
  PIN rw0_rd_out[60]
    DIRECTION OUTPUT ;
    USE SIGNAL ;
    SHAPE ABUTMENT ;
    PORT
      LAYER metal2 ;
      RECT 119.855 0.000 119.925 0.210 ;
    END
  END rw0_rd_out[60]
  PIN rw0_rd_out[61]
    DIRECTION OUTPUT ;
    USE SIGNAL ;
    SHAPE ABUTMENT ;
    PORT
      LAYER metal2 ;
      RECT 120.805 0.000 120.875 0.210 ;
    END
  END rw0_rd_out[61]
  PIN rw0_rd_out[62]
    DIRECTION OUTPUT ;
    USE SIGNAL ;
    SHAPE ABUTMENT ;
    PORT
      LAYER metal2 ;
      RECT 121.755 0.000 121.825 0.210 ;
    END
  END rw0_rd_out[62]
  PIN rw0_rd_out[63]
    DIRECTION OUTPUT ;
    USE SIGNAL ;
    SHAPE ABUTMENT ;
    PORT
      LAYER metal2 ;
      RECT 122.705 0.000 122.775 0.210 ;
    END
  END rw0_rd_out[63]
  PIN rw0_rd_out[64]
    DIRECTION OUTPUT ;
    USE SIGNAL ;
    SHAPE ABUTMENT ;
    PORT
      LAYER metal2 ;
      RECT 123.655 0.000 123.725 0.210 ;
    END
  END rw0_rd_out[64]
  PIN rw0_rd_out[65]
    DIRECTION OUTPUT ;
    USE SIGNAL ;
    SHAPE ABUTMENT ;
    PORT
      LAYER metal2 ;
      RECT 1.105 258.790 1.175 259.000 ;
    END
  END rw0_rd_out[65]
  PIN rw0_rd_out[66]
    DIRECTION OUTPUT ;
    USE SIGNAL ;
    SHAPE ABUTMENT ;
    PORT
      LAYER metal2 ;
      RECT 2.435 258.790 2.505 259.000 ;
    END
  END rw0_rd_out[66]
  PIN rw0_rd_out[67]
    DIRECTION OUTPUT ;
    USE SIGNAL ;
    SHAPE ABUTMENT ;
    PORT
      LAYER metal2 ;
      RECT 3.765 258.790 3.835 259.000 ;
    END
  END rw0_rd_out[67]
  PIN rw0_rd_out[68]
    DIRECTION OUTPUT ;
    USE SIGNAL ;
    SHAPE ABUTMENT ;
    PORT
      LAYER metal2 ;
      RECT 5.095 258.790 5.165 259.000 ;
    END
  END rw0_rd_out[68]
  PIN rw0_rd_out[69]
    DIRECTION OUTPUT ;
    USE SIGNAL ;
    SHAPE ABUTMENT ;
    PORT
      LAYER metal2 ;
      RECT 6.425 258.790 6.495 259.000 ;
    END
  END rw0_rd_out[69]
  PIN rw0_rd_out[70]
    DIRECTION OUTPUT ;
    USE SIGNAL ;
    SHAPE ABUTMENT ;
    PORT
      LAYER metal2 ;
      RECT 7.755 258.790 7.825 259.000 ;
    END
  END rw0_rd_out[70]
  PIN rw0_rd_out[71]
    DIRECTION OUTPUT ;
    USE SIGNAL ;
    SHAPE ABUTMENT ;
    PORT
      LAYER metal2 ;
      RECT 9.085 258.790 9.155 259.000 ;
    END
  END rw0_rd_out[71]
  PIN rw0_rd_out[72]
    DIRECTION OUTPUT ;
    USE SIGNAL ;
    SHAPE ABUTMENT ;
    PORT
      LAYER metal2 ;
      RECT 10.415 258.790 10.485 259.000 ;
    END
  END rw0_rd_out[72]
  PIN rw0_rd_out[73]
    DIRECTION OUTPUT ;
    USE SIGNAL ;
    SHAPE ABUTMENT ;
    PORT
      LAYER metal2 ;
      RECT 11.745 258.790 11.815 259.000 ;
    END
  END rw0_rd_out[73]
  PIN rw0_rd_out[74]
    DIRECTION OUTPUT ;
    USE SIGNAL ;
    SHAPE ABUTMENT ;
    PORT
      LAYER metal2 ;
      RECT 13.075 258.790 13.145 259.000 ;
    END
  END rw0_rd_out[74]
  PIN rw0_rd_out[75]
    DIRECTION OUTPUT ;
    USE SIGNAL ;
    SHAPE ABUTMENT ;
    PORT
      LAYER metal2 ;
      RECT 14.405 258.790 14.475 259.000 ;
    END
  END rw0_rd_out[75]
  PIN rw0_rd_out[76]
    DIRECTION OUTPUT ;
    USE SIGNAL ;
    SHAPE ABUTMENT ;
    PORT
      LAYER metal2 ;
      RECT 15.735 258.790 15.805 259.000 ;
    END
  END rw0_rd_out[76]
  PIN rw0_rd_out[77]
    DIRECTION OUTPUT ;
    USE SIGNAL ;
    SHAPE ABUTMENT ;
    PORT
      LAYER metal2 ;
      RECT 17.065 258.790 17.135 259.000 ;
    END
  END rw0_rd_out[77]
  PIN rw0_rd_out[78]
    DIRECTION OUTPUT ;
    USE SIGNAL ;
    SHAPE ABUTMENT ;
    PORT
      LAYER metal2 ;
      RECT 18.395 258.790 18.465 259.000 ;
    END
  END rw0_rd_out[78]
  PIN rw0_rd_out[79]
    DIRECTION OUTPUT ;
    USE SIGNAL ;
    SHAPE ABUTMENT ;
    PORT
      LAYER metal2 ;
      RECT 19.725 258.790 19.795 259.000 ;
    END
  END rw0_rd_out[79]
  PIN rw0_rd_out[80]
    DIRECTION OUTPUT ;
    USE SIGNAL ;
    SHAPE ABUTMENT ;
    PORT
      LAYER metal2 ;
      RECT 21.055 258.790 21.125 259.000 ;
    END
  END rw0_rd_out[80]
  PIN rw0_rd_out[81]
    DIRECTION OUTPUT ;
    USE SIGNAL ;
    SHAPE ABUTMENT ;
    PORT
      LAYER metal2 ;
      RECT 22.385 258.790 22.455 259.000 ;
    END
  END rw0_rd_out[81]
  PIN rw0_rd_out[82]
    DIRECTION OUTPUT ;
    USE SIGNAL ;
    SHAPE ABUTMENT ;
    PORT
      LAYER metal2 ;
      RECT 23.715 258.790 23.785 259.000 ;
    END
  END rw0_rd_out[82]
  PIN rw0_rd_out[83]
    DIRECTION OUTPUT ;
    USE SIGNAL ;
    SHAPE ABUTMENT ;
    PORT
      LAYER metal2 ;
      RECT 25.045 258.790 25.115 259.000 ;
    END
  END rw0_rd_out[83]
  PIN rw0_rd_out[84]
    DIRECTION OUTPUT ;
    USE SIGNAL ;
    SHAPE ABUTMENT ;
    PORT
      LAYER metal2 ;
      RECT 26.375 258.790 26.445 259.000 ;
    END
  END rw0_rd_out[84]
  PIN rw0_rd_out[85]
    DIRECTION OUTPUT ;
    USE SIGNAL ;
    SHAPE ABUTMENT ;
    PORT
      LAYER metal2 ;
      RECT 27.705 258.790 27.775 259.000 ;
    END
  END rw0_rd_out[85]
  PIN rw0_rd_out[86]
    DIRECTION OUTPUT ;
    USE SIGNAL ;
    SHAPE ABUTMENT ;
    PORT
      LAYER metal2 ;
      RECT 29.035 258.790 29.105 259.000 ;
    END
  END rw0_rd_out[86]
  PIN rw0_rd_out[87]
    DIRECTION OUTPUT ;
    USE SIGNAL ;
    SHAPE ABUTMENT ;
    PORT
      LAYER metal2 ;
      RECT 30.365 258.790 30.435 259.000 ;
    END
  END rw0_rd_out[87]
  PIN rw0_rd_out[88]
    DIRECTION OUTPUT ;
    USE SIGNAL ;
    SHAPE ABUTMENT ;
    PORT
      LAYER metal2 ;
      RECT 31.695 258.790 31.765 259.000 ;
    END
  END rw0_rd_out[88]
  PIN rw0_rd_out[89]
    DIRECTION OUTPUT ;
    USE SIGNAL ;
    SHAPE ABUTMENT ;
    PORT
      LAYER metal2 ;
      RECT 33.025 258.790 33.095 259.000 ;
    END
  END rw0_rd_out[89]
  PIN rw0_rd_out[90]
    DIRECTION OUTPUT ;
    USE SIGNAL ;
    SHAPE ABUTMENT ;
    PORT
      LAYER metal2 ;
      RECT 34.355 258.790 34.425 259.000 ;
    END
  END rw0_rd_out[90]
  PIN rw0_rd_out[91]
    DIRECTION OUTPUT ;
    USE SIGNAL ;
    SHAPE ABUTMENT ;
    PORT
      LAYER metal2 ;
      RECT 35.685 258.790 35.755 259.000 ;
    END
  END rw0_rd_out[91]
  PIN rw0_rd_out[92]
    DIRECTION OUTPUT ;
    USE SIGNAL ;
    SHAPE ABUTMENT ;
    PORT
      LAYER metal2 ;
      RECT 37.015 258.790 37.085 259.000 ;
    END
  END rw0_rd_out[92]
  PIN rw0_rd_out[93]
    DIRECTION OUTPUT ;
    USE SIGNAL ;
    SHAPE ABUTMENT ;
    PORT
      LAYER metal2 ;
      RECT 38.345 258.790 38.415 259.000 ;
    END
  END rw0_rd_out[93]
  PIN rw0_rd_out[94]
    DIRECTION OUTPUT ;
    USE SIGNAL ;
    SHAPE ABUTMENT ;
    PORT
      LAYER metal2 ;
      RECT 39.675 258.790 39.745 259.000 ;
    END
  END rw0_rd_out[94]
  PIN rw0_rd_out[95]
    DIRECTION OUTPUT ;
    USE SIGNAL ;
    SHAPE ABUTMENT ;
    PORT
      LAYER metal2 ;
      RECT 41.005 258.790 41.075 259.000 ;
    END
  END rw0_rd_out[95]
  PIN rw0_rd_out[96]
    DIRECTION OUTPUT ;
    USE SIGNAL ;
    SHAPE ABUTMENT ;
    PORT
      LAYER metal2 ;
      RECT 42.335 258.790 42.405 259.000 ;
    END
  END rw0_rd_out[96]
  PIN rw0_rd_out[97]
    DIRECTION OUTPUT ;
    USE SIGNAL ;
    SHAPE ABUTMENT ;
    PORT
      LAYER metal2 ;
      RECT 43.665 258.790 43.735 259.000 ;
    END
  END rw0_rd_out[97]
  PIN rw0_rd_out[98]
    DIRECTION OUTPUT ;
    USE SIGNAL ;
    SHAPE ABUTMENT ;
    PORT
      LAYER metal2 ;
      RECT 44.995 258.790 45.065 259.000 ;
    END
  END rw0_rd_out[98]
  PIN rw0_rd_out[99]
    DIRECTION OUTPUT ;
    USE SIGNAL ;
    SHAPE ABUTMENT ;
    PORT
      LAYER metal2 ;
      RECT 46.325 258.790 46.395 259.000 ;
    END
  END rw0_rd_out[99]
  PIN rw0_rd_out[100]
    DIRECTION OUTPUT ;
    USE SIGNAL ;
    SHAPE ABUTMENT ;
    PORT
      LAYER metal2 ;
      RECT 47.655 258.790 47.725 259.000 ;
    END
  END rw0_rd_out[100]
  PIN rw0_rd_out[101]
    DIRECTION OUTPUT ;
    USE SIGNAL ;
    SHAPE ABUTMENT ;
    PORT
      LAYER metal2 ;
      RECT 48.985 258.790 49.055 259.000 ;
    END
  END rw0_rd_out[101]
  PIN rw0_rd_out[102]
    DIRECTION OUTPUT ;
    USE SIGNAL ;
    SHAPE ABUTMENT ;
    PORT
      LAYER metal2 ;
      RECT 50.315 258.790 50.385 259.000 ;
    END
  END rw0_rd_out[102]
  PIN rw0_rd_out[103]
    DIRECTION OUTPUT ;
    USE SIGNAL ;
    SHAPE ABUTMENT ;
    PORT
      LAYER metal2 ;
      RECT 51.645 258.790 51.715 259.000 ;
    END
  END rw0_rd_out[103]
  PIN rw0_rd_out[104]
    DIRECTION OUTPUT ;
    USE SIGNAL ;
    SHAPE ABUTMENT ;
    PORT
      LAYER metal2 ;
      RECT 52.975 258.790 53.045 259.000 ;
    END
  END rw0_rd_out[104]
  PIN rw0_rd_out[105]
    DIRECTION OUTPUT ;
    USE SIGNAL ;
    SHAPE ABUTMENT ;
    PORT
      LAYER metal2 ;
      RECT 54.305 258.790 54.375 259.000 ;
    END
  END rw0_rd_out[105]
  PIN rw0_rd_out[106]
    DIRECTION OUTPUT ;
    USE SIGNAL ;
    SHAPE ABUTMENT ;
    PORT
      LAYER metal2 ;
      RECT 55.635 258.790 55.705 259.000 ;
    END
  END rw0_rd_out[106]
  PIN rw0_rd_out[107]
    DIRECTION OUTPUT ;
    USE SIGNAL ;
    SHAPE ABUTMENT ;
    PORT
      LAYER metal2 ;
      RECT 56.965 258.790 57.035 259.000 ;
    END
  END rw0_rd_out[107]
  PIN rw0_rd_out[108]
    DIRECTION OUTPUT ;
    USE SIGNAL ;
    SHAPE ABUTMENT ;
    PORT
      LAYER metal2 ;
      RECT 58.295 258.790 58.365 259.000 ;
    END
  END rw0_rd_out[108]
  PIN rw0_rd_out[109]
    DIRECTION OUTPUT ;
    USE SIGNAL ;
    SHAPE ABUTMENT ;
    PORT
      LAYER metal2 ;
      RECT 59.625 258.790 59.695 259.000 ;
    END
  END rw0_rd_out[109]
  PIN rw0_rd_out[110]
    DIRECTION OUTPUT ;
    USE SIGNAL ;
    SHAPE ABUTMENT ;
    PORT
      LAYER metal2 ;
      RECT 60.955 258.790 61.025 259.000 ;
    END
  END rw0_rd_out[110]
  PIN rw0_rd_out[111]
    DIRECTION OUTPUT ;
    USE SIGNAL ;
    SHAPE ABUTMENT ;
    PORT
      LAYER metal2 ;
      RECT 62.285 258.790 62.355 259.000 ;
    END
  END rw0_rd_out[111]
  PIN rw0_rd_out[112]
    DIRECTION OUTPUT ;
    USE SIGNAL ;
    SHAPE ABUTMENT ;
    PORT
      LAYER metal2 ;
      RECT 63.615 258.790 63.685 259.000 ;
    END
  END rw0_rd_out[112]
  PIN rw0_rd_out[113]
    DIRECTION OUTPUT ;
    USE SIGNAL ;
    SHAPE ABUTMENT ;
    PORT
      LAYER metal2 ;
      RECT 64.945 258.790 65.015 259.000 ;
    END
  END rw0_rd_out[113]
  PIN rw0_rd_out[114]
    DIRECTION OUTPUT ;
    USE SIGNAL ;
    SHAPE ABUTMENT ;
    PORT
      LAYER metal2 ;
      RECT 66.275 258.790 66.345 259.000 ;
    END
  END rw0_rd_out[114]
  PIN rw0_rd_out[115]
    DIRECTION OUTPUT ;
    USE SIGNAL ;
    SHAPE ABUTMENT ;
    PORT
      LAYER metal2 ;
      RECT 67.605 258.790 67.675 259.000 ;
    END
  END rw0_rd_out[115]
  PIN rw0_rd_out[116]
    DIRECTION OUTPUT ;
    USE SIGNAL ;
    SHAPE ABUTMENT ;
    PORT
      LAYER metal2 ;
      RECT 68.935 258.790 69.005 259.000 ;
    END
  END rw0_rd_out[116]
  PIN rw0_rd_out[117]
    DIRECTION OUTPUT ;
    USE SIGNAL ;
    SHAPE ABUTMENT ;
    PORT
      LAYER metal2 ;
      RECT 70.265 258.790 70.335 259.000 ;
    END
  END rw0_rd_out[117]
  PIN rw0_rd_out[118]
    DIRECTION OUTPUT ;
    USE SIGNAL ;
    SHAPE ABUTMENT ;
    PORT
      LAYER metal2 ;
      RECT 71.595 258.790 71.665 259.000 ;
    END
  END rw0_rd_out[118]
  PIN rw0_rd_out[119]
    DIRECTION OUTPUT ;
    USE SIGNAL ;
    SHAPE ABUTMENT ;
    PORT
      LAYER metal2 ;
      RECT 72.925 258.790 72.995 259.000 ;
    END
  END rw0_rd_out[119]
  PIN rw0_rd_out[120]
    DIRECTION OUTPUT ;
    USE SIGNAL ;
    SHAPE ABUTMENT ;
    PORT
      LAYER metal2 ;
      RECT 74.255 258.790 74.325 259.000 ;
    END
  END rw0_rd_out[120]
  PIN rw0_rd_out[121]
    DIRECTION OUTPUT ;
    USE SIGNAL ;
    SHAPE ABUTMENT ;
    PORT
      LAYER metal2 ;
      RECT 75.585 258.790 75.655 259.000 ;
    END
  END rw0_rd_out[121]
  PIN rw0_rd_out[122]
    DIRECTION OUTPUT ;
    USE SIGNAL ;
    SHAPE ABUTMENT ;
    PORT
      LAYER metal2 ;
      RECT 76.915 258.790 76.985 259.000 ;
    END
  END rw0_rd_out[122]
  PIN rw0_rd_out[123]
    DIRECTION OUTPUT ;
    USE SIGNAL ;
    SHAPE ABUTMENT ;
    PORT
      LAYER metal2 ;
      RECT 78.245 258.790 78.315 259.000 ;
    END
  END rw0_rd_out[123]
  PIN rw0_rd_out[124]
    DIRECTION OUTPUT ;
    USE SIGNAL ;
    SHAPE ABUTMENT ;
    PORT
      LAYER metal2 ;
      RECT 79.575 258.790 79.645 259.000 ;
    END
  END rw0_rd_out[124]
  PIN rw0_rd_out[125]
    DIRECTION OUTPUT ;
    USE SIGNAL ;
    SHAPE ABUTMENT ;
    PORT
      LAYER metal2 ;
      RECT 80.905 258.790 80.975 259.000 ;
    END
  END rw0_rd_out[125]
  PIN rw0_rd_out[126]
    DIRECTION OUTPUT ;
    USE SIGNAL ;
    SHAPE ABUTMENT ;
    PORT
      LAYER metal2 ;
      RECT 82.235 258.790 82.305 259.000 ;
    END
  END rw0_rd_out[126]
  PIN rw0_rd_out[127]
    DIRECTION OUTPUT ;
    USE SIGNAL ;
    SHAPE ABUTMENT ;
    PORT
      LAYER metal2 ;
      RECT 83.565 258.790 83.635 259.000 ;
    END
  END rw0_rd_out[127]
  PIN rw0_rd_out[128]
    DIRECTION OUTPUT ;
    USE SIGNAL ;
    SHAPE ABUTMENT ;
    PORT
      LAYER metal2 ;
      RECT 84.895 258.790 84.965 259.000 ;
    END
  END rw0_rd_out[128]
  PIN rw0_rd_out[129]
    DIRECTION OUTPUT ;
    USE SIGNAL ;
    SHAPE ABUTMENT ;
    PORT
      LAYER metal2 ;
      RECT 86.225 258.790 86.295 259.000 ;
    END
  END rw0_rd_out[129]
  PIN r0_rd_out[0]
    DIRECTION OUTPUT ;
    USE SIGNAL ;
    SHAPE ABUTMENT ;
    PORT
      LAYER metal2 ;
      RECT 124.605 0.000 124.675 0.210 ;
    END
  END r0_rd_out[0]
  PIN r0_rd_out[1]
    DIRECTION OUTPUT ;
    USE SIGNAL ;
    SHAPE ABUTMENT ;
    PORT
      LAYER metal2 ;
      RECT 125.555 0.000 125.625 0.210 ;
    END
  END r0_rd_out[1]
  PIN r0_rd_out[2]
    DIRECTION OUTPUT ;
    USE SIGNAL ;
    SHAPE ABUTMENT ;
    PORT
      LAYER metal2 ;
      RECT 126.505 0.000 126.575 0.210 ;
    END
  END r0_rd_out[2]
  PIN r0_rd_out[3]
    DIRECTION OUTPUT ;
    USE SIGNAL ;
    SHAPE ABUTMENT ;
    PORT
      LAYER metal2 ;
      RECT 127.455 0.000 127.525 0.210 ;
    END
  END r0_rd_out[3]
  PIN r0_rd_out[4]
    DIRECTION OUTPUT ;
    USE SIGNAL ;
    SHAPE ABUTMENT ;
    PORT
      LAYER metal2 ;
      RECT 128.405 0.000 128.475 0.210 ;
    END
  END r0_rd_out[4]
  PIN r0_rd_out[5]
    DIRECTION OUTPUT ;
    USE SIGNAL ;
    SHAPE ABUTMENT ;
    PORT
      LAYER metal2 ;
      RECT 129.355 0.000 129.425 0.210 ;
    END
  END r0_rd_out[5]
  PIN r0_rd_out[6]
    DIRECTION OUTPUT ;
    USE SIGNAL ;
    SHAPE ABUTMENT ;
    PORT
      LAYER metal2 ;
      RECT 130.305 0.000 130.375 0.210 ;
    END
  END r0_rd_out[6]
  PIN r0_rd_out[7]
    DIRECTION OUTPUT ;
    USE SIGNAL ;
    SHAPE ABUTMENT ;
    PORT
      LAYER metal2 ;
      RECT 131.255 0.000 131.325 0.210 ;
    END
  END r0_rd_out[7]
  PIN r0_rd_out[8]
    DIRECTION OUTPUT ;
    USE SIGNAL ;
    SHAPE ABUTMENT ;
    PORT
      LAYER metal2 ;
      RECT 132.205 0.000 132.275 0.210 ;
    END
  END r0_rd_out[8]
  PIN r0_rd_out[9]
    DIRECTION OUTPUT ;
    USE SIGNAL ;
    SHAPE ABUTMENT ;
    PORT
      LAYER metal2 ;
      RECT 133.155 0.000 133.225 0.210 ;
    END
  END r0_rd_out[9]
  PIN r0_rd_out[10]
    DIRECTION OUTPUT ;
    USE SIGNAL ;
    SHAPE ABUTMENT ;
    PORT
      LAYER metal2 ;
      RECT 134.105 0.000 134.175 0.210 ;
    END
  END r0_rd_out[10]
  PIN r0_rd_out[11]
    DIRECTION OUTPUT ;
    USE SIGNAL ;
    SHAPE ABUTMENT ;
    PORT
      LAYER metal2 ;
      RECT 135.055 0.000 135.125 0.210 ;
    END
  END r0_rd_out[11]
  PIN r0_rd_out[12]
    DIRECTION OUTPUT ;
    USE SIGNAL ;
    SHAPE ABUTMENT ;
    PORT
      LAYER metal2 ;
      RECT 136.005 0.000 136.075 0.210 ;
    END
  END r0_rd_out[12]
  PIN r0_rd_out[13]
    DIRECTION OUTPUT ;
    USE SIGNAL ;
    SHAPE ABUTMENT ;
    PORT
      LAYER metal2 ;
      RECT 136.955 0.000 137.025 0.210 ;
    END
  END r0_rd_out[13]
  PIN r0_rd_out[14]
    DIRECTION OUTPUT ;
    USE SIGNAL ;
    SHAPE ABUTMENT ;
    PORT
      LAYER metal2 ;
      RECT 137.905 0.000 137.975 0.210 ;
    END
  END r0_rd_out[14]
  PIN r0_rd_out[15]
    DIRECTION OUTPUT ;
    USE SIGNAL ;
    SHAPE ABUTMENT ;
    PORT
      LAYER metal2 ;
      RECT 138.855 0.000 138.925 0.210 ;
    END
  END r0_rd_out[15]
  PIN r0_rd_out[16]
    DIRECTION OUTPUT ;
    USE SIGNAL ;
    SHAPE ABUTMENT ;
    PORT
      LAYER metal2 ;
      RECT 139.805 0.000 139.875 0.210 ;
    END
  END r0_rd_out[16]
  PIN r0_rd_out[17]
    DIRECTION OUTPUT ;
    USE SIGNAL ;
    SHAPE ABUTMENT ;
    PORT
      LAYER metal2 ;
      RECT 140.755 0.000 140.825 0.210 ;
    END
  END r0_rd_out[17]
  PIN r0_rd_out[18]
    DIRECTION OUTPUT ;
    USE SIGNAL ;
    SHAPE ABUTMENT ;
    PORT
      LAYER metal2 ;
      RECT 141.705 0.000 141.775 0.210 ;
    END
  END r0_rd_out[18]
  PIN r0_rd_out[19]
    DIRECTION OUTPUT ;
    USE SIGNAL ;
    SHAPE ABUTMENT ;
    PORT
      LAYER metal2 ;
      RECT 142.655 0.000 142.725 0.210 ;
    END
  END r0_rd_out[19]
  PIN r0_rd_out[20]
    DIRECTION OUTPUT ;
    USE SIGNAL ;
    SHAPE ABUTMENT ;
    PORT
      LAYER metal2 ;
      RECT 143.605 0.000 143.675 0.210 ;
    END
  END r0_rd_out[20]
  PIN r0_rd_out[21]
    DIRECTION OUTPUT ;
    USE SIGNAL ;
    SHAPE ABUTMENT ;
    PORT
      LAYER metal2 ;
      RECT 144.555 0.000 144.625 0.210 ;
    END
  END r0_rd_out[21]
  PIN r0_rd_out[22]
    DIRECTION OUTPUT ;
    USE SIGNAL ;
    SHAPE ABUTMENT ;
    PORT
      LAYER metal2 ;
      RECT 145.505 0.000 145.575 0.210 ;
    END
  END r0_rd_out[22]
  PIN r0_rd_out[23]
    DIRECTION OUTPUT ;
    USE SIGNAL ;
    SHAPE ABUTMENT ;
    PORT
      LAYER metal2 ;
      RECT 146.455 0.000 146.525 0.210 ;
    END
  END r0_rd_out[23]
  PIN r0_rd_out[24]
    DIRECTION OUTPUT ;
    USE SIGNAL ;
    SHAPE ABUTMENT ;
    PORT
      LAYER metal2 ;
      RECT 147.405 0.000 147.475 0.210 ;
    END
  END r0_rd_out[24]
  PIN r0_rd_out[25]
    DIRECTION OUTPUT ;
    USE SIGNAL ;
    SHAPE ABUTMENT ;
    PORT
      LAYER metal2 ;
      RECT 148.355 0.000 148.425 0.210 ;
    END
  END r0_rd_out[25]
  PIN r0_rd_out[26]
    DIRECTION OUTPUT ;
    USE SIGNAL ;
    SHAPE ABUTMENT ;
    PORT
      LAYER metal2 ;
      RECT 149.305 0.000 149.375 0.210 ;
    END
  END r0_rd_out[26]
  PIN r0_rd_out[27]
    DIRECTION OUTPUT ;
    USE SIGNAL ;
    SHAPE ABUTMENT ;
    PORT
      LAYER metal2 ;
      RECT 150.255 0.000 150.325 0.210 ;
    END
  END r0_rd_out[27]
  PIN r0_rd_out[28]
    DIRECTION OUTPUT ;
    USE SIGNAL ;
    SHAPE ABUTMENT ;
    PORT
      LAYER metal2 ;
      RECT 151.205 0.000 151.275 0.210 ;
    END
  END r0_rd_out[28]
  PIN r0_rd_out[29]
    DIRECTION OUTPUT ;
    USE SIGNAL ;
    SHAPE ABUTMENT ;
    PORT
      LAYER metal2 ;
      RECT 152.155 0.000 152.225 0.210 ;
    END
  END r0_rd_out[29]
  PIN r0_rd_out[30]
    DIRECTION OUTPUT ;
    USE SIGNAL ;
    SHAPE ABUTMENT ;
    PORT
      LAYER metal2 ;
      RECT 153.105 0.000 153.175 0.210 ;
    END
  END r0_rd_out[30]
  PIN r0_rd_out[31]
    DIRECTION OUTPUT ;
    USE SIGNAL ;
    SHAPE ABUTMENT ;
    PORT
      LAYER metal2 ;
      RECT 154.055 0.000 154.125 0.210 ;
    END
  END r0_rd_out[31]
  PIN r0_rd_out[32]
    DIRECTION OUTPUT ;
    USE SIGNAL ;
    SHAPE ABUTMENT ;
    PORT
      LAYER metal2 ;
      RECT 155.005 0.000 155.075 0.210 ;
    END
  END r0_rd_out[32]
  PIN r0_rd_out[33]
    DIRECTION OUTPUT ;
    USE SIGNAL ;
    SHAPE ABUTMENT ;
    PORT
      LAYER metal2 ;
      RECT 155.955 0.000 156.025 0.210 ;
    END
  END r0_rd_out[33]
  PIN r0_rd_out[34]
    DIRECTION OUTPUT ;
    USE SIGNAL ;
    SHAPE ABUTMENT ;
    PORT
      LAYER metal2 ;
      RECT 156.905 0.000 156.975 0.210 ;
    END
  END r0_rd_out[34]
  PIN r0_rd_out[35]
    DIRECTION OUTPUT ;
    USE SIGNAL ;
    SHAPE ABUTMENT ;
    PORT
      LAYER metal2 ;
      RECT 157.855 0.000 157.925 0.210 ;
    END
  END r0_rd_out[35]
  PIN r0_rd_out[36]
    DIRECTION OUTPUT ;
    USE SIGNAL ;
    SHAPE ABUTMENT ;
    PORT
      LAYER metal2 ;
      RECT 158.805 0.000 158.875 0.210 ;
    END
  END r0_rd_out[36]
  PIN r0_rd_out[37]
    DIRECTION OUTPUT ;
    USE SIGNAL ;
    SHAPE ABUTMENT ;
    PORT
      LAYER metal2 ;
      RECT 159.755 0.000 159.825 0.210 ;
    END
  END r0_rd_out[37]
  PIN r0_rd_out[38]
    DIRECTION OUTPUT ;
    USE SIGNAL ;
    SHAPE ABUTMENT ;
    PORT
      LAYER metal2 ;
      RECT 160.705 0.000 160.775 0.210 ;
    END
  END r0_rd_out[38]
  PIN r0_rd_out[39]
    DIRECTION OUTPUT ;
    USE SIGNAL ;
    SHAPE ABUTMENT ;
    PORT
      LAYER metal2 ;
      RECT 161.655 0.000 161.725 0.210 ;
    END
  END r0_rd_out[39]
  PIN r0_rd_out[40]
    DIRECTION OUTPUT ;
    USE SIGNAL ;
    SHAPE ABUTMENT ;
    PORT
      LAYER metal2 ;
      RECT 162.605 0.000 162.675 0.210 ;
    END
  END r0_rd_out[40]
  PIN r0_rd_out[41]
    DIRECTION OUTPUT ;
    USE SIGNAL ;
    SHAPE ABUTMENT ;
    PORT
      LAYER metal2 ;
      RECT 163.555 0.000 163.625 0.210 ;
    END
  END r0_rd_out[41]
  PIN r0_rd_out[42]
    DIRECTION OUTPUT ;
    USE SIGNAL ;
    SHAPE ABUTMENT ;
    PORT
      LAYER metal2 ;
      RECT 164.505 0.000 164.575 0.210 ;
    END
  END r0_rd_out[42]
  PIN r0_rd_out[43]
    DIRECTION OUTPUT ;
    USE SIGNAL ;
    SHAPE ABUTMENT ;
    PORT
      LAYER metal2 ;
      RECT 165.455 0.000 165.525 0.210 ;
    END
  END r0_rd_out[43]
  PIN r0_rd_out[44]
    DIRECTION OUTPUT ;
    USE SIGNAL ;
    SHAPE ABUTMENT ;
    PORT
      LAYER metal2 ;
      RECT 166.405 0.000 166.475 0.210 ;
    END
  END r0_rd_out[44]
  PIN r0_rd_out[45]
    DIRECTION OUTPUT ;
    USE SIGNAL ;
    SHAPE ABUTMENT ;
    PORT
      LAYER metal2 ;
      RECT 167.355 0.000 167.425 0.210 ;
    END
  END r0_rd_out[45]
  PIN r0_rd_out[46]
    DIRECTION OUTPUT ;
    USE SIGNAL ;
    SHAPE ABUTMENT ;
    PORT
      LAYER metal2 ;
      RECT 168.305 0.000 168.375 0.210 ;
    END
  END r0_rd_out[46]
  PIN r0_rd_out[47]
    DIRECTION OUTPUT ;
    USE SIGNAL ;
    SHAPE ABUTMENT ;
    PORT
      LAYER metal2 ;
      RECT 169.255 0.000 169.325 0.210 ;
    END
  END r0_rd_out[47]
  PIN r0_rd_out[48]
    DIRECTION OUTPUT ;
    USE SIGNAL ;
    SHAPE ABUTMENT ;
    PORT
      LAYER metal2 ;
      RECT 170.205 0.000 170.275 0.210 ;
    END
  END r0_rd_out[48]
  PIN r0_rd_out[49]
    DIRECTION OUTPUT ;
    USE SIGNAL ;
    SHAPE ABUTMENT ;
    PORT
      LAYER metal2 ;
      RECT 171.155 0.000 171.225 0.210 ;
    END
  END r0_rd_out[49]
  PIN r0_rd_out[50]
    DIRECTION OUTPUT ;
    USE SIGNAL ;
    SHAPE ABUTMENT ;
    PORT
      LAYER metal2 ;
      RECT 172.105 0.000 172.175 0.210 ;
    END
  END r0_rd_out[50]
  PIN r0_rd_out[51]
    DIRECTION OUTPUT ;
    USE SIGNAL ;
    SHAPE ABUTMENT ;
    PORT
      LAYER metal2 ;
      RECT 173.055 0.000 173.125 0.210 ;
    END
  END r0_rd_out[51]
  PIN r0_rd_out[52]
    DIRECTION OUTPUT ;
    USE SIGNAL ;
    SHAPE ABUTMENT ;
    PORT
      LAYER metal2 ;
      RECT 174.005 0.000 174.075 0.210 ;
    END
  END r0_rd_out[52]
  PIN r0_rd_out[53]
    DIRECTION OUTPUT ;
    USE SIGNAL ;
    SHAPE ABUTMENT ;
    PORT
      LAYER metal2 ;
      RECT 174.955 0.000 175.025 0.210 ;
    END
  END r0_rd_out[53]
  PIN r0_rd_out[54]
    DIRECTION OUTPUT ;
    USE SIGNAL ;
    SHAPE ABUTMENT ;
    PORT
      LAYER metal2 ;
      RECT 175.905 0.000 175.975 0.210 ;
    END
  END r0_rd_out[54]
  PIN r0_rd_out[55]
    DIRECTION OUTPUT ;
    USE SIGNAL ;
    SHAPE ABUTMENT ;
    PORT
      LAYER metal2 ;
      RECT 176.855 0.000 176.925 0.210 ;
    END
  END r0_rd_out[55]
  PIN r0_rd_out[56]
    DIRECTION OUTPUT ;
    USE SIGNAL ;
    SHAPE ABUTMENT ;
    PORT
      LAYER metal2 ;
      RECT 177.805 0.000 177.875 0.210 ;
    END
  END r0_rd_out[56]
  PIN r0_rd_out[57]
    DIRECTION OUTPUT ;
    USE SIGNAL ;
    SHAPE ABUTMENT ;
    PORT
      LAYER metal2 ;
      RECT 178.755 0.000 178.825 0.210 ;
    END
  END r0_rd_out[57]
  PIN r0_rd_out[58]
    DIRECTION OUTPUT ;
    USE SIGNAL ;
    SHAPE ABUTMENT ;
    PORT
      LAYER metal2 ;
      RECT 179.705 0.000 179.775 0.210 ;
    END
  END r0_rd_out[58]
  PIN r0_rd_out[59]
    DIRECTION OUTPUT ;
    USE SIGNAL ;
    SHAPE ABUTMENT ;
    PORT
      LAYER metal2 ;
      RECT 180.655 0.000 180.725 0.210 ;
    END
  END r0_rd_out[59]
  PIN r0_rd_out[60]
    DIRECTION OUTPUT ;
    USE SIGNAL ;
    SHAPE ABUTMENT ;
    PORT
      LAYER metal2 ;
      RECT 181.605 0.000 181.675 0.210 ;
    END
  END r0_rd_out[60]
  PIN r0_rd_out[61]
    DIRECTION OUTPUT ;
    USE SIGNAL ;
    SHAPE ABUTMENT ;
    PORT
      LAYER metal2 ;
      RECT 182.555 0.000 182.625 0.210 ;
    END
  END r0_rd_out[61]
  PIN r0_rd_out[62]
    DIRECTION OUTPUT ;
    USE SIGNAL ;
    SHAPE ABUTMENT ;
    PORT
      LAYER metal2 ;
      RECT 183.505 0.000 183.575 0.210 ;
    END
  END r0_rd_out[62]
  PIN r0_rd_out[63]
    DIRECTION OUTPUT ;
    USE SIGNAL ;
    SHAPE ABUTMENT ;
    PORT
      LAYER metal2 ;
      RECT 184.455 0.000 184.525 0.210 ;
    END
  END r0_rd_out[63]
  PIN r0_rd_out[64]
    DIRECTION OUTPUT ;
    USE SIGNAL ;
    SHAPE ABUTMENT ;
    PORT
      LAYER metal2 ;
      RECT 185.405 0.000 185.475 0.210 ;
    END
  END r0_rd_out[64]
  PIN r0_rd_out[65]
    DIRECTION OUTPUT ;
    USE SIGNAL ;
    SHAPE ABUTMENT ;
    PORT
      LAYER metal2 ;
      RECT 87.555 258.790 87.625 259.000 ;
    END
  END r0_rd_out[65]
  PIN r0_rd_out[66]
    DIRECTION OUTPUT ;
    USE SIGNAL ;
    SHAPE ABUTMENT ;
    PORT
      LAYER metal2 ;
      RECT 88.885 258.790 88.955 259.000 ;
    END
  END r0_rd_out[66]
  PIN r0_rd_out[67]
    DIRECTION OUTPUT ;
    USE SIGNAL ;
    SHAPE ABUTMENT ;
    PORT
      LAYER metal2 ;
      RECT 90.215 258.790 90.285 259.000 ;
    END
  END r0_rd_out[67]
  PIN r0_rd_out[68]
    DIRECTION OUTPUT ;
    USE SIGNAL ;
    SHAPE ABUTMENT ;
    PORT
      LAYER metal2 ;
      RECT 91.545 258.790 91.615 259.000 ;
    END
  END r0_rd_out[68]
  PIN r0_rd_out[69]
    DIRECTION OUTPUT ;
    USE SIGNAL ;
    SHAPE ABUTMENT ;
    PORT
      LAYER metal2 ;
      RECT 92.875 258.790 92.945 259.000 ;
    END
  END r0_rd_out[69]
  PIN r0_rd_out[70]
    DIRECTION OUTPUT ;
    USE SIGNAL ;
    SHAPE ABUTMENT ;
    PORT
      LAYER metal2 ;
      RECT 94.205 258.790 94.275 259.000 ;
    END
  END r0_rd_out[70]
  PIN r0_rd_out[71]
    DIRECTION OUTPUT ;
    USE SIGNAL ;
    SHAPE ABUTMENT ;
    PORT
      LAYER metal2 ;
      RECT 95.535 258.790 95.605 259.000 ;
    END
  END r0_rd_out[71]
  PIN r0_rd_out[72]
    DIRECTION OUTPUT ;
    USE SIGNAL ;
    SHAPE ABUTMENT ;
    PORT
      LAYER metal2 ;
      RECT 96.865 258.790 96.935 259.000 ;
    END
  END r0_rd_out[72]
  PIN r0_rd_out[73]
    DIRECTION OUTPUT ;
    USE SIGNAL ;
    SHAPE ABUTMENT ;
    PORT
      LAYER metal2 ;
      RECT 98.195 258.790 98.265 259.000 ;
    END
  END r0_rd_out[73]
  PIN r0_rd_out[74]
    DIRECTION OUTPUT ;
    USE SIGNAL ;
    SHAPE ABUTMENT ;
    PORT
      LAYER metal2 ;
      RECT 99.525 258.790 99.595 259.000 ;
    END
  END r0_rd_out[74]
  PIN r0_rd_out[75]
    DIRECTION OUTPUT ;
    USE SIGNAL ;
    SHAPE ABUTMENT ;
    PORT
      LAYER metal2 ;
      RECT 100.855 258.790 100.925 259.000 ;
    END
  END r0_rd_out[75]
  PIN r0_rd_out[76]
    DIRECTION OUTPUT ;
    USE SIGNAL ;
    SHAPE ABUTMENT ;
    PORT
      LAYER metal2 ;
      RECT 102.185 258.790 102.255 259.000 ;
    END
  END r0_rd_out[76]
  PIN r0_rd_out[77]
    DIRECTION OUTPUT ;
    USE SIGNAL ;
    SHAPE ABUTMENT ;
    PORT
      LAYER metal2 ;
      RECT 103.515 258.790 103.585 259.000 ;
    END
  END r0_rd_out[77]
  PIN r0_rd_out[78]
    DIRECTION OUTPUT ;
    USE SIGNAL ;
    SHAPE ABUTMENT ;
    PORT
      LAYER metal2 ;
      RECT 104.845 258.790 104.915 259.000 ;
    END
  END r0_rd_out[78]
  PIN r0_rd_out[79]
    DIRECTION OUTPUT ;
    USE SIGNAL ;
    SHAPE ABUTMENT ;
    PORT
      LAYER metal2 ;
      RECT 106.175 258.790 106.245 259.000 ;
    END
  END r0_rd_out[79]
  PIN r0_rd_out[80]
    DIRECTION OUTPUT ;
    USE SIGNAL ;
    SHAPE ABUTMENT ;
    PORT
      LAYER metal2 ;
      RECT 107.505 258.790 107.575 259.000 ;
    END
  END r0_rd_out[80]
  PIN r0_rd_out[81]
    DIRECTION OUTPUT ;
    USE SIGNAL ;
    SHAPE ABUTMENT ;
    PORT
      LAYER metal2 ;
      RECT 108.835 258.790 108.905 259.000 ;
    END
  END r0_rd_out[81]
  PIN r0_rd_out[82]
    DIRECTION OUTPUT ;
    USE SIGNAL ;
    SHAPE ABUTMENT ;
    PORT
      LAYER metal2 ;
      RECT 110.165 258.790 110.235 259.000 ;
    END
  END r0_rd_out[82]
  PIN r0_rd_out[83]
    DIRECTION OUTPUT ;
    USE SIGNAL ;
    SHAPE ABUTMENT ;
    PORT
      LAYER metal2 ;
      RECT 111.495 258.790 111.565 259.000 ;
    END
  END r0_rd_out[83]
  PIN r0_rd_out[84]
    DIRECTION OUTPUT ;
    USE SIGNAL ;
    SHAPE ABUTMENT ;
    PORT
      LAYER metal2 ;
      RECT 112.825 258.790 112.895 259.000 ;
    END
  END r0_rd_out[84]
  PIN r0_rd_out[85]
    DIRECTION OUTPUT ;
    USE SIGNAL ;
    SHAPE ABUTMENT ;
    PORT
      LAYER metal2 ;
      RECT 114.155 258.790 114.225 259.000 ;
    END
  END r0_rd_out[85]
  PIN r0_rd_out[86]
    DIRECTION OUTPUT ;
    USE SIGNAL ;
    SHAPE ABUTMENT ;
    PORT
      LAYER metal2 ;
      RECT 115.485 258.790 115.555 259.000 ;
    END
  END r0_rd_out[86]
  PIN r0_rd_out[87]
    DIRECTION OUTPUT ;
    USE SIGNAL ;
    SHAPE ABUTMENT ;
    PORT
      LAYER metal2 ;
      RECT 116.815 258.790 116.885 259.000 ;
    END
  END r0_rd_out[87]
  PIN r0_rd_out[88]
    DIRECTION OUTPUT ;
    USE SIGNAL ;
    SHAPE ABUTMENT ;
    PORT
      LAYER metal2 ;
      RECT 118.145 258.790 118.215 259.000 ;
    END
  END r0_rd_out[88]
  PIN r0_rd_out[89]
    DIRECTION OUTPUT ;
    USE SIGNAL ;
    SHAPE ABUTMENT ;
    PORT
      LAYER metal2 ;
      RECT 119.475 258.790 119.545 259.000 ;
    END
  END r0_rd_out[89]
  PIN r0_rd_out[90]
    DIRECTION OUTPUT ;
    USE SIGNAL ;
    SHAPE ABUTMENT ;
    PORT
      LAYER metal2 ;
      RECT 120.805 258.790 120.875 259.000 ;
    END
  END r0_rd_out[90]
  PIN r0_rd_out[91]
    DIRECTION OUTPUT ;
    USE SIGNAL ;
    SHAPE ABUTMENT ;
    PORT
      LAYER metal2 ;
      RECT 122.135 258.790 122.205 259.000 ;
    END
  END r0_rd_out[91]
  PIN r0_rd_out[92]
    DIRECTION OUTPUT ;
    USE SIGNAL ;
    SHAPE ABUTMENT ;
    PORT
      LAYER metal2 ;
      RECT 123.465 258.790 123.535 259.000 ;
    END
  END r0_rd_out[92]
  PIN r0_rd_out[93]
    DIRECTION OUTPUT ;
    USE SIGNAL ;
    SHAPE ABUTMENT ;
    PORT
      LAYER metal2 ;
      RECT 124.795 258.790 124.865 259.000 ;
    END
  END r0_rd_out[93]
  PIN r0_rd_out[94]
    DIRECTION OUTPUT ;
    USE SIGNAL ;
    SHAPE ABUTMENT ;
    PORT
      LAYER metal2 ;
      RECT 126.125 258.790 126.195 259.000 ;
    END
  END r0_rd_out[94]
  PIN r0_rd_out[95]
    DIRECTION OUTPUT ;
    USE SIGNAL ;
    SHAPE ABUTMENT ;
    PORT
      LAYER metal2 ;
      RECT 127.455 258.790 127.525 259.000 ;
    END
  END r0_rd_out[95]
  PIN r0_rd_out[96]
    DIRECTION OUTPUT ;
    USE SIGNAL ;
    SHAPE ABUTMENT ;
    PORT
      LAYER metal2 ;
      RECT 128.785 258.790 128.855 259.000 ;
    END
  END r0_rd_out[96]
  PIN r0_rd_out[97]
    DIRECTION OUTPUT ;
    USE SIGNAL ;
    SHAPE ABUTMENT ;
    PORT
      LAYER metal2 ;
      RECT 130.115 258.790 130.185 259.000 ;
    END
  END r0_rd_out[97]
  PIN r0_rd_out[98]
    DIRECTION OUTPUT ;
    USE SIGNAL ;
    SHAPE ABUTMENT ;
    PORT
      LAYER metal2 ;
      RECT 131.445 258.790 131.515 259.000 ;
    END
  END r0_rd_out[98]
  PIN r0_rd_out[99]
    DIRECTION OUTPUT ;
    USE SIGNAL ;
    SHAPE ABUTMENT ;
    PORT
      LAYER metal2 ;
      RECT 132.775 258.790 132.845 259.000 ;
    END
  END r0_rd_out[99]
  PIN r0_rd_out[100]
    DIRECTION OUTPUT ;
    USE SIGNAL ;
    SHAPE ABUTMENT ;
    PORT
      LAYER metal2 ;
      RECT 134.105 258.790 134.175 259.000 ;
    END
  END r0_rd_out[100]
  PIN r0_rd_out[101]
    DIRECTION OUTPUT ;
    USE SIGNAL ;
    SHAPE ABUTMENT ;
    PORT
      LAYER metal2 ;
      RECT 135.435 258.790 135.505 259.000 ;
    END
  END r0_rd_out[101]
  PIN r0_rd_out[102]
    DIRECTION OUTPUT ;
    USE SIGNAL ;
    SHAPE ABUTMENT ;
    PORT
      LAYER metal2 ;
      RECT 136.765 258.790 136.835 259.000 ;
    END
  END r0_rd_out[102]
  PIN r0_rd_out[103]
    DIRECTION OUTPUT ;
    USE SIGNAL ;
    SHAPE ABUTMENT ;
    PORT
      LAYER metal2 ;
      RECT 138.095 258.790 138.165 259.000 ;
    END
  END r0_rd_out[103]
  PIN r0_rd_out[104]
    DIRECTION OUTPUT ;
    USE SIGNAL ;
    SHAPE ABUTMENT ;
    PORT
      LAYER metal2 ;
      RECT 139.425 258.790 139.495 259.000 ;
    END
  END r0_rd_out[104]
  PIN r0_rd_out[105]
    DIRECTION OUTPUT ;
    USE SIGNAL ;
    SHAPE ABUTMENT ;
    PORT
      LAYER metal2 ;
      RECT 140.755 258.790 140.825 259.000 ;
    END
  END r0_rd_out[105]
  PIN r0_rd_out[106]
    DIRECTION OUTPUT ;
    USE SIGNAL ;
    SHAPE ABUTMENT ;
    PORT
      LAYER metal2 ;
      RECT 142.085 258.790 142.155 259.000 ;
    END
  END r0_rd_out[106]
  PIN r0_rd_out[107]
    DIRECTION OUTPUT ;
    USE SIGNAL ;
    SHAPE ABUTMENT ;
    PORT
      LAYER metal2 ;
      RECT 143.415 258.790 143.485 259.000 ;
    END
  END r0_rd_out[107]
  PIN r0_rd_out[108]
    DIRECTION OUTPUT ;
    USE SIGNAL ;
    SHAPE ABUTMENT ;
    PORT
      LAYER metal2 ;
      RECT 144.745 258.790 144.815 259.000 ;
    END
  END r0_rd_out[108]
  PIN r0_rd_out[109]
    DIRECTION OUTPUT ;
    USE SIGNAL ;
    SHAPE ABUTMENT ;
    PORT
      LAYER metal2 ;
      RECT 146.075 258.790 146.145 259.000 ;
    END
  END r0_rd_out[109]
  PIN r0_rd_out[110]
    DIRECTION OUTPUT ;
    USE SIGNAL ;
    SHAPE ABUTMENT ;
    PORT
      LAYER metal2 ;
      RECT 147.405 258.790 147.475 259.000 ;
    END
  END r0_rd_out[110]
  PIN r0_rd_out[111]
    DIRECTION OUTPUT ;
    USE SIGNAL ;
    SHAPE ABUTMENT ;
    PORT
      LAYER metal2 ;
      RECT 148.735 258.790 148.805 259.000 ;
    END
  END r0_rd_out[111]
  PIN r0_rd_out[112]
    DIRECTION OUTPUT ;
    USE SIGNAL ;
    SHAPE ABUTMENT ;
    PORT
      LAYER metal2 ;
      RECT 150.065 258.790 150.135 259.000 ;
    END
  END r0_rd_out[112]
  PIN r0_rd_out[113]
    DIRECTION OUTPUT ;
    USE SIGNAL ;
    SHAPE ABUTMENT ;
    PORT
      LAYER metal2 ;
      RECT 151.395 258.790 151.465 259.000 ;
    END
  END r0_rd_out[113]
  PIN r0_rd_out[114]
    DIRECTION OUTPUT ;
    USE SIGNAL ;
    SHAPE ABUTMENT ;
    PORT
      LAYER metal2 ;
      RECT 152.725 258.790 152.795 259.000 ;
    END
  END r0_rd_out[114]
  PIN r0_rd_out[115]
    DIRECTION OUTPUT ;
    USE SIGNAL ;
    SHAPE ABUTMENT ;
    PORT
      LAYER metal2 ;
      RECT 154.055 258.790 154.125 259.000 ;
    END
  END r0_rd_out[115]
  PIN r0_rd_out[116]
    DIRECTION OUTPUT ;
    USE SIGNAL ;
    SHAPE ABUTMENT ;
    PORT
      LAYER metal2 ;
      RECT 155.385 258.790 155.455 259.000 ;
    END
  END r0_rd_out[116]
  PIN r0_rd_out[117]
    DIRECTION OUTPUT ;
    USE SIGNAL ;
    SHAPE ABUTMENT ;
    PORT
      LAYER metal2 ;
      RECT 156.715 258.790 156.785 259.000 ;
    END
  END r0_rd_out[117]
  PIN r0_rd_out[118]
    DIRECTION OUTPUT ;
    USE SIGNAL ;
    SHAPE ABUTMENT ;
    PORT
      LAYER metal2 ;
      RECT 158.045 258.790 158.115 259.000 ;
    END
  END r0_rd_out[118]
  PIN r0_rd_out[119]
    DIRECTION OUTPUT ;
    USE SIGNAL ;
    SHAPE ABUTMENT ;
    PORT
      LAYER metal2 ;
      RECT 159.375 258.790 159.445 259.000 ;
    END
  END r0_rd_out[119]
  PIN r0_rd_out[120]
    DIRECTION OUTPUT ;
    USE SIGNAL ;
    SHAPE ABUTMENT ;
    PORT
      LAYER metal2 ;
      RECT 160.705 258.790 160.775 259.000 ;
    END
  END r0_rd_out[120]
  PIN r0_rd_out[121]
    DIRECTION OUTPUT ;
    USE SIGNAL ;
    SHAPE ABUTMENT ;
    PORT
      LAYER metal2 ;
      RECT 162.035 258.790 162.105 259.000 ;
    END
  END r0_rd_out[121]
  PIN r0_rd_out[122]
    DIRECTION OUTPUT ;
    USE SIGNAL ;
    SHAPE ABUTMENT ;
    PORT
      LAYER metal2 ;
      RECT 163.365 258.790 163.435 259.000 ;
    END
  END r0_rd_out[122]
  PIN r0_rd_out[123]
    DIRECTION OUTPUT ;
    USE SIGNAL ;
    SHAPE ABUTMENT ;
    PORT
      LAYER metal2 ;
      RECT 164.695 258.790 164.765 259.000 ;
    END
  END r0_rd_out[123]
  PIN r0_rd_out[124]
    DIRECTION OUTPUT ;
    USE SIGNAL ;
    SHAPE ABUTMENT ;
    PORT
      LAYER metal2 ;
      RECT 166.025 258.790 166.095 259.000 ;
    END
  END r0_rd_out[124]
  PIN r0_rd_out[125]
    DIRECTION OUTPUT ;
    USE SIGNAL ;
    SHAPE ABUTMENT ;
    PORT
      LAYER metal2 ;
      RECT 167.355 258.790 167.425 259.000 ;
    END
  END r0_rd_out[125]
  PIN r0_rd_out[126]
    DIRECTION OUTPUT ;
    USE SIGNAL ;
    SHAPE ABUTMENT ;
    PORT
      LAYER metal2 ;
      RECT 168.685 258.790 168.755 259.000 ;
    END
  END r0_rd_out[126]
  PIN r0_rd_out[127]
    DIRECTION OUTPUT ;
    USE SIGNAL ;
    SHAPE ABUTMENT ;
    PORT
      LAYER metal2 ;
      RECT 170.015 258.790 170.085 259.000 ;
    END
  END r0_rd_out[127]
  PIN r0_rd_out[128]
    DIRECTION OUTPUT ;
    USE SIGNAL ;
    SHAPE ABUTMENT ;
    PORT
      LAYER metal2 ;
      RECT 171.345 258.790 171.415 259.000 ;
    END
  END r0_rd_out[128]
  PIN r0_rd_out[129]
    DIRECTION OUTPUT ;
    USE SIGNAL ;
    SHAPE ABUTMENT ;
    PORT
      LAYER metal2 ;
      RECT 172.675 258.790 172.745 259.000 ;
    END
  END r0_rd_out[129]
  PIN rw0_addr_in[0]
    DIRECTION INPUT ;
    USE SIGNAL ;
    SHAPE ABUTMENT ;
    PORT
      LAYER metal3 ;
      RECT 0.000 208.705 0.210 208.775 ;
    END
  END rw0_addr_in[0]
  PIN rw0_addr_in[1]
    DIRECTION INPUT ;
    USE SIGNAL ;
    SHAPE ABUTMENT ;
    PORT
      LAYER metal3 ;
      RECT 0.000 215.005 0.210 215.075 ;
    END
  END rw0_addr_in[1]
  PIN rw0_addr_in[2]
    DIRECTION INPUT ;
    USE SIGNAL ;
    SHAPE ABUTMENT ;
    PORT
      LAYER metal3 ;
      RECT 0.000 221.305 0.210 221.375 ;
    END
  END rw0_addr_in[2]
  PIN rw0_addr_in[3]
    DIRECTION INPUT ;
    USE SIGNAL ;
    SHAPE ABUTMENT ;
    PORT
      LAYER metal3 ;
      RECT 0.000 227.605 0.210 227.675 ;
    END
  END rw0_addr_in[3]
  PIN rw0_addr_in[4]
    DIRECTION INPUT ;
    USE SIGNAL ;
    SHAPE ABUTMENT ;
    PORT
      LAYER metal3 ;
      RECT 188.080 202.405 188.290 202.475 ;
    END
  END rw0_addr_in[4]
  PIN rw0_addr_in[5]
    DIRECTION INPUT ;
    USE SIGNAL ;
    SHAPE ABUTMENT ;
    PORT
      LAYER metal3 ;
      RECT 188.080 208.705 188.290 208.775 ;
    END
  END rw0_addr_in[5]
  PIN rw0_addr_in[6]
    DIRECTION INPUT ;
    USE SIGNAL ;
    SHAPE ABUTMENT ;
    PORT
      LAYER metal3 ;
      RECT 188.080 215.005 188.290 215.075 ;
    END
  END rw0_addr_in[6]
  PIN r0_addr_in[0]
    DIRECTION INPUT ;
    USE SIGNAL ;
    SHAPE ABUTMENT ;
    PORT
      LAYER metal3 ;
      RECT 0.000 233.905 0.210 233.975 ;
    END
  END r0_addr_in[0]
  PIN r0_addr_in[1]
    DIRECTION INPUT ;
    USE SIGNAL ;
    SHAPE ABUTMENT ;
    PORT
      LAYER metal3 ;
      RECT 0.000 240.205 0.210 240.275 ;
    END
  END r0_addr_in[1]
  PIN r0_addr_in[2]
    DIRECTION INPUT ;
    USE SIGNAL ;
    SHAPE ABUTMENT ;
    PORT
      LAYER metal3 ;
      RECT 0.000 246.505 0.210 246.575 ;
    END
  END r0_addr_in[2]
  PIN r0_addr_in[3]
    DIRECTION INPUT ;
    USE SIGNAL ;
    SHAPE ABUTMENT ;
    PORT
      LAYER metal3 ;
      RECT 0.000 252.805 0.210 252.875 ;
    END
  END r0_addr_in[3]
  PIN r0_addr_in[4]
    DIRECTION INPUT ;
    USE SIGNAL ;
    SHAPE ABUTMENT ;
    PORT
      LAYER metal3 ;
      RECT 188.080 221.305 188.290 221.375 ;
    END
  END r0_addr_in[4]
  PIN r0_addr_in[5]
    DIRECTION INPUT ;
    USE SIGNAL ;
    SHAPE ABUTMENT ;
    PORT
      LAYER metal3 ;
      RECT 188.080 227.605 188.290 227.675 ;
    END
  END r0_addr_in[5]
  PIN r0_addr_in[6]
    DIRECTION INPUT ;
    USE SIGNAL ;
    SHAPE ABUTMENT ;
    PORT
      LAYER metal3 ;
      RECT 188.080 233.905 188.290 233.975 ;
    END
  END r0_addr_in[6]
  PIN rw0_we_in
    DIRECTION INPUT ;
    USE SIGNAL ;
    SHAPE ABUTMENT ;
    PORT
      LAYER metal2 ;
      RECT 174.005 258.790 174.075 259.000 ;
    END
  END rw0_we_in
  PIN rw0_ce_in
    DIRECTION INPUT ;
    USE SIGNAL ;
    SHAPE ABUTMENT ;
    PORT
      LAYER metal2 ;
      RECT 175.335 258.790 175.405 259.000 ;
    END
  END rw0_ce_in
  PIN rw0_clk
    DIRECTION INPUT ;
    USE SIGNAL ;
    SHAPE ABUTMENT ;
    PORT
      LAYER metal2 ;
      RECT 176.665 258.790 176.735 259.000 ;
    END
  END rw0_clk
  PIN r0_ce_in
    DIRECTION INPUT ;
    USE SIGNAL ;
    SHAPE ABUTMENT ;
    PORT
      LAYER metal2 ;
      RECT 177.995 258.790 178.065 259.000 ;
    END
  END r0_ce_in
  PIN r0_clk
    DIRECTION INPUT ;
    USE SIGNAL ;
    SHAPE ABUTMENT ;
    PORT
      LAYER metal2 ;
      RECT 179.325 258.790 179.395 259.000 ;
    END
  END r0_clk
  PIN VSS
    DIRECTION INOUT ;
    USE GROUND ;
    PORT
      LAYER metal4 ;
      RECT 1.000 0.840 1.280 258.160 ;
      RECT 3.240 0.840 3.520 258.160 ;
      RECT 5.480 0.840 5.760 258.160 ;
      RECT 7.720 0.840 8.000 258.160 ;
      RECT 9.960 0.840 10.240 258.160 ;
      RECT 12.200 0.840 12.480 258.160 ;
      RECT 14.440 0.840 14.720 258.160 ;
      RECT 16.680 0.840 16.960 258.160 ;
      RECT 18.920 0.840 19.200 258.160 ;
      RECT 21.160 0.840 21.440 258.160 ;
      RECT 23.400 0.840 23.680 258.160 ;
      RECT 25.640 0.840 25.920 258.160 ;
      RECT 27.880 0.840 28.160 258.160 ;
      RECT 30.120 0.840 30.400 258.160 ;
      RECT 32.360 0.840 32.640 258.160 ;
      RECT 34.600 0.840 34.880 258.160 ;
      RECT 36.840 0.840 37.120 258.160 ;
      RECT 39.080 0.840 39.360 258.160 ;
      RECT 41.320 0.840 41.600 258.160 ;
      RECT 43.560 0.840 43.840 258.160 ;
      RECT 45.800 0.840 46.080 258.160 ;
      RECT 48.040 0.840 48.320 258.160 ;
      RECT 50.280 0.840 50.560 258.160 ;
      RECT 52.520 0.840 52.800 258.160 ;
      RECT 54.760 0.840 55.040 258.160 ;
      RECT 57.000 0.840 57.280 258.160 ;
      RECT 59.240 0.840 59.520 258.160 ;
      RECT 61.480 0.840 61.760 258.160 ;
      RECT 63.720 0.840 64.000 258.160 ;
      RECT 65.960 0.840 66.240 258.160 ;
      RECT 68.200 0.840 68.480 258.160 ;
      RECT 70.440 0.840 70.720 258.160 ;
      RECT 72.680 0.840 72.960 258.160 ;
      RECT 74.920 0.840 75.200 258.160 ;
      RECT 77.160 0.840 77.440 258.160 ;
      RECT 79.400 0.840 79.680 258.160 ;
      RECT 81.640 0.840 81.920 258.160 ;
      RECT 83.880 0.840 84.160 258.160 ;
      RECT 86.120 0.840 86.400 258.160 ;
      RECT 88.360 0.840 88.640 258.160 ;
      RECT 90.600 0.840 90.880 258.160 ;
      RECT 92.840 0.840 93.120 258.160 ;
      RECT 95.080 0.840 95.360 258.160 ;
      RECT 97.320 0.840 97.600 258.160 ;
      RECT 99.560 0.840 99.840 258.160 ;
      RECT 101.800 0.840 102.080 258.160 ;
      RECT 104.040 0.840 104.320 258.160 ;
      RECT 106.280 0.840 106.560 258.160 ;
      RECT 108.520 0.840 108.800 258.160 ;
      RECT 110.760 0.840 111.040 258.160 ;
      RECT 113.000 0.840 113.280 258.160 ;
      RECT 115.240 0.840 115.520 258.160 ;
      RECT 117.480 0.840 117.760 258.160 ;
      RECT 119.720 0.840 120.000 258.160 ;
      RECT 121.960 0.840 122.240 258.160 ;
      RECT 124.200 0.840 124.480 258.160 ;
      RECT 126.440 0.840 126.720 258.160 ;
      RECT 128.680 0.840 128.960 258.160 ;
      RECT 130.920 0.840 131.200 258.160 ;
      RECT 133.160 0.840 133.440 258.160 ;
      RECT 135.400 0.840 135.680 258.160 ;
      RECT 137.640 0.840 137.920 258.160 ;
      RECT 139.880 0.840 140.160 258.160 ;
      RECT 142.120 0.840 142.400 258.160 ;
      RECT 144.360 0.840 144.640 258.160 ;
      RECT 146.600 0.840 146.880 258.160 ;
      RECT 148.840 0.840 149.120 258.160 ;
      RECT 151.080 0.840 151.360 258.160 ;
      RECT 153.320 0.840 153.600 258.160 ;
      RECT 155.560 0.840 155.840 258.160 ;
      RECT 157.800 0.840 158.080 258.160 ;
      RECT 160.040 0.840 160.320 258.160 ;
      RECT 162.280 0.840 162.560 258.160 ;
      RECT 164.520 0.840 164.800 258.160 ;
      RECT 166.760 0.840 167.040 258.160 ;
      RECT 169.000 0.840 169.280 258.160 ;
      RECT 171.240 0.840 171.520 258.160 ;
      RECT 173.480 0.840 173.760 258.160 ;
      RECT 175.720 0.840 176.000 258.160 ;
      RECT 177.960 0.840 178.240 258.160 ;
      RECT 180.200 0.840 180.480 258.160 ;
      RECT 182.440 0.840 182.720 258.160 ;
      RECT 184.680 0.840 184.960 258.160 ;
      RECT 186.920 0.840 187.200 258.160 ;
    END
  END VSS
  PIN VDD
    DIRECTION INOUT ;
    USE POWER ;
    PORT
      LAYER metal4 ;
      RECT 2.120 0.840 2.400 258.160 ;
      RECT 4.360 0.840 4.640 258.160 ;
      RECT 6.600 0.840 6.880 258.160 ;
      RECT 8.840 0.840 9.120 258.160 ;
      RECT 11.080 0.840 11.360 258.160 ;
      RECT 13.320 0.840 13.600 258.160 ;
      RECT 15.560 0.840 15.840 258.160 ;
      RECT 17.800 0.840 18.080 258.160 ;
      RECT 20.040 0.840 20.320 258.160 ;
      RECT 22.280 0.840 22.560 258.160 ;
      RECT 24.520 0.840 24.800 258.160 ;
      RECT 26.760 0.840 27.040 258.160 ;
      RECT 29.000 0.840 29.280 258.160 ;
      RECT 31.240 0.840 31.520 258.160 ;
      RECT 33.480 0.840 33.760 258.160 ;
      RECT 35.720 0.840 36.000 258.160 ;
      RECT 37.960 0.840 38.240 258.160 ;
      RECT 40.200 0.840 40.480 258.160 ;
      RECT 42.440 0.840 42.720 258.160 ;
      RECT 44.680 0.840 44.960 258.160 ;
      RECT 46.920 0.840 47.200 258.160 ;
      RECT 49.160 0.840 49.440 258.160 ;
      RECT 51.400 0.840 51.680 258.160 ;
      RECT 53.640 0.840 53.920 258.160 ;
      RECT 55.880 0.840 56.160 258.160 ;
      RECT 58.120 0.840 58.400 258.160 ;
      RECT 60.360 0.840 60.640 258.160 ;
      RECT 62.600 0.840 62.880 258.160 ;
      RECT 64.840 0.840 65.120 258.160 ;
      RECT 67.080 0.840 67.360 258.160 ;
      RECT 69.320 0.840 69.600 258.160 ;
      RECT 71.560 0.840 71.840 258.160 ;
      RECT 73.800 0.840 74.080 258.160 ;
      RECT 76.040 0.840 76.320 258.160 ;
      RECT 78.280 0.840 78.560 258.160 ;
      RECT 80.520 0.840 80.800 258.160 ;
      RECT 82.760 0.840 83.040 258.160 ;
      RECT 85.000 0.840 85.280 258.160 ;
      RECT 87.240 0.840 87.520 258.160 ;
      RECT 89.480 0.840 89.760 258.160 ;
      RECT 91.720 0.840 92.000 258.160 ;
      RECT 93.960 0.840 94.240 258.160 ;
      RECT 96.200 0.840 96.480 258.160 ;
      RECT 98.440 0.840 98.720 258.160 ;
      RECT 100.680 0.840 100.960 258.160 ;
      RECT 102.920 0.840 103.200 258.160 ;
      RECT 105.160 0.840 105.440 258.160 ;
      RECT 107.400 0.840 107.680 258.160 ;
      RECT 109.640 0.840 109.920 258.160 ;
      RECT 111.880 0.840 112.160 258.160 ;
      RECT 114.120 0.840 114.400 258.160 ;
      RECT 116.360 0.840 116.640 258.160 ;
      RECT 118.600 0.840 118.880 258.160 ;
      RECT 120.840 0.840 121.120 258.160 ;
      RECT 123.080 0.840 123.360 258.160 ;
      RECT 125.320 0.840 125.600 258.160 ;
      RECT 127.560 0.840 127.840 258.160 ;
      RECT 129.800 0.840 130.080 258.160 ;
      RECT 132.040 0.840 132.320 258.160 ;
      RECT 134.280 0.840 134.560 258.160 ;
      RECT 136.520 0.840 136.800 258.160 ;
      RECT 138.760 0.840 139.040 258.160 ;
      RECT 141.000 0.840 141.280 258.160 ;
      RECT 143.240 0.840 143.520 258.160 ;
      RECT 145.480 0.840 145.760 258.160 ;
      RECT 147.720 0.840 148.000 258.160 ;
      RECT 149.960 0.840 150.240 258.160 ;
      RECT 152.200 0.840 152.480 258.160 ;
      RECT 154.440 0.840 154.720 258.160 ;
      RECT 156.680 0.840 156.960 258.160 ;
      RECT 158.920 0.840 159.200 258.160 ;
      RECT 161.160 0.840 161.440 258.160 ;
      RECT 163.400 0.840 163.680 258.160 ;
      RECT 165.640 0.840 165.920 258.160 ;
      RECT 167.880 0.840 168.160 258.160 ;
      RECT 170.120 0.840 170.400 258.160 ;
      RECT 172.360 0.840 172.640 258.160 ;
      RECT 174.600 0.840 174.880 258.160 ;
      RECT 176.840 0.840 177.120 258.160 ;
      RECT 179.080 0.840 179.360 258.160 ;
      RECT 181.320 0.840 181.600 258.160 ;
      RECT 183.560 0.840 183.840 258.160 ;
      RECT 185.800 0.840 186.080 258.160 ;
    END
  END VDD
  OBS
    LAYER metal1 ;
    RECT 0 0 188.290 259.000 ;
    LAYER metal2 ;
    RECT 0 0 188.290 259.000 ;
    LAYER metal3 ;
    RECT 0 0 188.290 259.000 ;
    LAYER metal4 ;
    RECT 0 0 188.290 259.000 ;
    LAYER OVERLAP ;
    RECT 0 0 188.290 259.000 ;
  END
END fakeram_1rw1r_130w128d_sram

END LIBRARY
